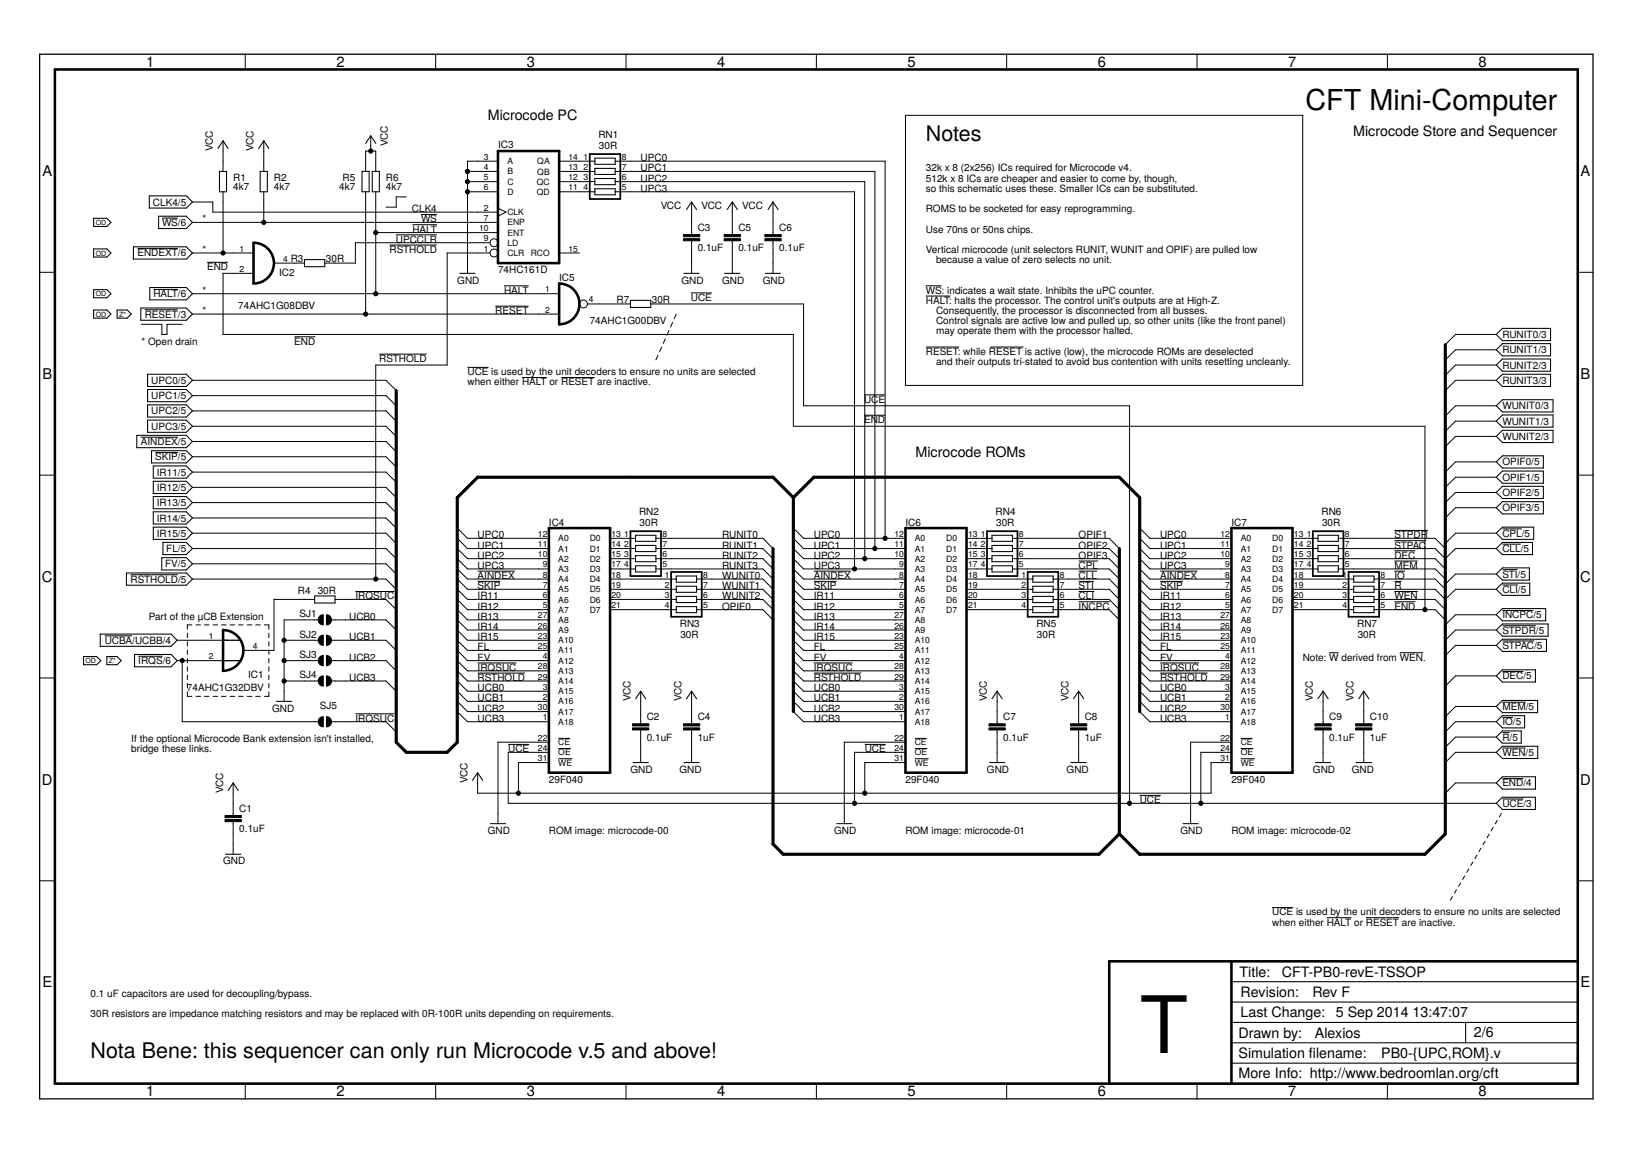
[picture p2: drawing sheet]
<svg xmlns="http://www.w3.org/2000/svg" width="297mm" height="210mm" viewBox="0 0 297 210" stroke-linecap="round" stroke-linejoin="round" font-family="sans-serif">
<defs><g id="words">
<text font-size="14.4" x="207.4" y="191.5">T</text>
<text font-size="5.2" x="237.6" y="20.1">CFT Mini-Computer</text>
<g font-size="3.9">
<text x="168.5" y="25.6">Notes</text>
<text x="16.5" y="192.5">Nota Bene: this sequencer can only run Microcode v.5 and above!</text>
</g>
<g font-size="2.7">
<text x="26.6" y="12.2">1</text>
<text x="61.2" y="12.2">2</text>
<text x="95.9" y="12.2">3</text>
<text x="130.5" y="12.2">4</text>
<text x="165.2" y="12.2">5</text>
<text x="199.8" y="12.2">6</text>
<text x="234.5" y="12.2">7</text>
<text x="269.1" y="12.2">8</text>
<text x="7.7" y="32">A</text>
<text x="287.7" y="32">A</text>
<text x="7.7" y="68.9">B</text>
<text x="287.7" y="68.9">B</text>
<text x="7.6" y="105.8">C</text>
<text x="287.6" y="105.8">C</text>
<text x="7.6" y="142.7">D</text>
<text x="287.6" y="142.7">D</text>
<text x="7.7" y="179.6">E</text>
<text x="287.7" y="179.6">E</text>
<text x="26.6" y="199.4">1</text>
<text x="61.2" y="199.4">2</text>
<text x="95.9" y="199.4">3</text>
<text x="130.5" y="199.4">4</text>
<text x="165.2" y="199.4">5</text>
<text x="199.8" y="199.4">6</text>
<text x="234.5" y="199.4">7</text>
<text x="269.1" y="199.4">8</text>
</g>
<g font-size="2.6">
<text x="88.8" y="21.9">Microcode PC</text>
<text x="246.3" y="24.7">Microcode Store and Sequencer</text>
<text x="166.7" y="83.1">Microcode ROMs</text>
<text x="225.6" y="177.6">Title:</text>
<text x="233.3" y="177.7">CFT-PB0-revE-TSSOP</text>
<text x="225.8" y="181.3">Revision:</text>
<text x="225.8" y="185">Last Change:</text>
<text x="238.9" y="181.4">Rev F</text>
<text x="243.1" y="185">5 Sep 2014</text>
<text x="257.1" y="185">13:47:07</text>
<text x="225.4" y="188.8">Drawn by:</text>
<text x="239.3" y="188.8">Alexios</text>
<text x="268.3" y="188.7">2/6</text>
<text x="225.4" y="192.5">Simulation flename:</text>
<text x="225.4" y="196.2">More Info: http://www.bedroomlan.org/cft</text>
<text x="238.2" y="192.5">i</text>
<text x="251.4" y="192.5">PB0-{UPC,ROM}.v</text>
</g>
<g font-size="1.8">
<text x="38.7" y="27.5" transform="rotate(-90 38.7 27.5)">VCC</text>
<text x="46.2" y="27.5" transform="rotate(-90 46.2 27.5)">VCC</text>
<text x="70.6" y="26.5" transform="rotate(-90 70.6 26.5)">VCC</text>
<text x="90.6" y="27">IC3</text>
<text x="108.9" y="25.1">RN1</text>
<text x="109" y="27.1">30R</text>
<text x="116.6" y="29.3">UPC0</text>
<text x="42.4" y="34.5">4k7</text>
<text x="42.4" y="32.9">R1</text>
<text x="49.9" y="34.5">4k7</text>
<text x="49.9" y="32.9">R2</text>
<text x="61.7" y="34.5">4k7</text>
<text x="62.4" y="32.9">R5</text>
<text x="70.3" y="34.5">4k7</text>
<text x="70.3" y="32.9">R6</text>
<text x="116.6" y="31.2">UPC1</text>
<text x="116.6" y="33">UPC2</text>
<text x="116.6" y="34.9">UPC3</text>
<text x="168.5" y="31.2">32k x 8 (2x256) ICs required for Microcode v4.</text>
<text x="168.5" y="33">512k x 8 ICs are cheaper and easier to come by, though,</text>
<text x="168.5" y="34.9">so this schematic uses these. Smaller ICs can be substituted.</text>
<text x="27.8" y="37.4">CLK4/5</text>
<text x="29.5" y="41.1">WS/6</text>
<text x="36.9" y="40.4">*</text>
<text x="75" y="38.6">CLK4</text>
<text x="76.6" y="40.4">WS</text>
<text x="120.3" y="38">VCC</text>
<text x="127.7" y="38">VCC</text>
<text x="135.1" y="38">VCC</text>
<text x="168.5" y="38.6">ROMS to be socketed for easy reprogramming.</text>
<text x="25" y="46.7">ENDEXT/6</text>
<text x="36.9" y="46">*</text>
<text x="52.9" y="47.7">R3</text>
<text x="59.3" y="47.7">30R</text>
<text x="70.9" y="46">RSTHOLD</text>
<text x="72" y="44.2">UPCCLR</text>
<text x="75.1" y="42.3">HALT</text>
<text x="127" y="45.7">0.1uF</text>
<text x="127" y="42">C3</text>
<text x="134.4" y="45.7">0.1uF</text>
<text x="134.4" y="42">C5</text>
<text x="141.8" y="45.7">0.1uF</text>
<text x="141.8" y="42">C6</text>
<text x="168.5" y="42.3">Use 70ns or 50ns chips.</text>
<text x="168.5" y="46">Vertical microcode (unit selectors RUNIT, WUNIT and OPIF) are pulled low</text>
<text x="170.4" y="47.9">because a value of zero selects no unit.</text>
<text x="36.9" y="53.4">*</text>
<text x="37.7" y="49.2">END</text>
<text x="50.8" y="50.2">IC2</text>
<text x="83.2" y="51.6">GND</text>
<text x="90.6" y="49.7">74HC161D</text>
<text x="91.7" y="53.4">HALT</text>
<text x="101.8" y="51.1">IC5</text>
<text x="124" y="51.6">GND</text>
<text x="131.4" y="51.6">GND</text>
<text x="138.8" y="51.6">GND</text>
<text x="168.5" y="53.4">WS: indicates a wait state. Inhibits the uPC counter.</text>
<text x="26.3" y="57.8">RESET/3</text>
<text x="27.9" y="54.1">HALT/6</text>
<text x="36.9" y="57.1">*</text>
<text x="43.4" y="56.2">74AHC1G08DBV</text>
<text x="90.2" y="57.1">RESET</text>
<text x="107.3" y="59">74AHC1G00DBV</text>
<text x="112.2" y="55.1">R7</text>
<text x="118.6" y="55.1">30R</text>
<text x="125.7" y="54.7">UCE</text>
<text x="168.5" y="55.3">HALT: halts the processor. The control unit's outputs are at High-Z.</text>
<text x="170.4" y="57.1">Consequently, the processor is disconnected from all busses.</text>
<text x="170.4" y="59">Control signals are active low and pulled up, so other units (like the front panel)</text>
<text x="25.8" y="62.7">* Open drain</text>
<text x="53.6" y="62.7">END</text>
<text x="69" y="65.8">RSTHOLD</text>
<text x="168.5" y="64.5">RESET: while RESET is active (low), the microcode ROMs are deselected</text>
<text x="170.4" y="60.8">may operate them with the processor halted.</text>
<text x="273.4" y="61.5">RUNIT0/3</text>
<text x="273.4" y="64.3">RUNIT1/3</text>
<text x="27.5" y="69.8">UPC0/5</text>
<text x="85.1" y="68.3">UCE is used by the unit decoders to ensure no units are selected</text>
<text x="85.1" y="70.1">when either HALT or RESET are inactive.</text>
<text x="170.4" y="66.4">and their outputs tri-stated to avoid bus contention with units resetting uncleanly.</text>
<text x="273.4" y="67.1">RUNIT2/3</text>
<text x="273.4" y="69.8">RUNIT3/3</text>
<text x="27.5" y="72.6">UPC1/5</text>
<text x="27.5" y="75.4">UPC2/5</text>
<text x="157.3" y="77">EN</text>
<text x="157.3" y="73.3">UCE</text>
<text x="159.8" y="77">D</text>
<text x="273.4" y="74.5">WUNIT0/3</text>
<text x="273.4" y="77.2">WUNIT1/3</text>
<text x="25.6" y="81">AINDEX/5</text>
<text x="27.5" y="78.2">UPC3/5</text>
<text x="28.3" y="83.7">SKIP/5</text>
<text x="273.4" y="80">WUNIT2/3</text>
<text x="28.5" y="86.5">IR11/5</text>
<text x="28.5" y="89.3">IR12/5</text>
<text x="273.4" y="84.7">OPIF0/5</text>
<text x="273.4" y="87.4">OPIF1/5</text>
<text x="28.5" y="92.1">IR13/5</text>
<text x="28.5" y="94.9">IR14/5</text>
<text x="99.9" y="95.6">IC4</text>
<text x="116.3" y="93.7">RN2</text>
<text x="116.4" y="95.7">30R</text>
<text x="164.8" y="95.6">IC6</text>
<text x="181.2" y="93.7">RN4</text>
<text x="181.3" y="95.7">30R</text>
<text x="224.1" y="95.6">IC7</text>
<text x="240.5" y="93.7">RN6</text>
<text x="240.6" y="95.7">30R</text>
<text x="273.4" y="90.2">OPIF2/5</text>
<text x="273.4" y="93">OPIF3/5</text>
<text x="28.5" y="97.6">IR15/5</text>
<text x="30.3" y="100.4">FL/5</text>
<text x="86.9" y="97.9">UPC0</text>
<text x="86.9" y="99.8">UPC1</text>
<text x="86.9" y="101.6">UPC2</text>
<text x="131.4" y="97.9">RUNIT0</text>
<text x="131.4" y="99.8">RUNIT1</text>
<text x="131.4" y="101.6">RUNIT2</text>
<text x="148.1" y="97.9">UPC0</text>
<text x="148.1" y="99.8">UPC1</text>
<text x="148.1" y="101.6">UPC2</text>
<text x="196.3" y="97.9">OPIF1</text>
<text x="196.3" y="99.8">OPIF2</text>
<text x="196.3" y="101.6">OPIF3</text>
<text x="211.2" y="97.9">UPC0</text>
<text x="211.2" y="99.8">UPC1</text>
<text x="211.2" y="101.6">UPC2</text>
<text x="253.8" y="97.9">STPDR</text>
<text x="253.8" y="99.8">STPAC</text>
<text x="253.8" y="101.6">DEC</text>
<text x="273.4" y="100.4">CLL/5</text>
<text x="273.4" y="97.6">CPL/5</text>
<text x="23.8" y="106">RSTHOLD/5</text>
<text x="30.1" y="103.2">FV/5</text>
<text x="86.9" y="105.3">AINDEX</text>
<text x="86.9" y="107.2">SKIP</text>
<text x="86.9" y="103.5">UPC3</text>
<text x="131.4" y="103.5">RUNIT3</text>
<text x="131.4" y="105.3">WUNIT0</text>
<text x="131.4" y="107.2">WUNIT1</text>
<text x="148.1" y="105.3">AINDEX</text>
<text x="148.1" y="107.2">SKIP</text>
<text x="148.1" y="103.5">UPC3</text>
<text x="196.3" y="107.2">STI</text>
<text x="196.3" y="105.3">CLL</text>
<text x="196.3" y="103.5">CPL</text>
<text x="211.2" y="105.3">AINDEX</text>
<text x="211.2" y="107.2">SKIP</text>
<text x="211.2" y="103.5">UPC3</text>
<text x="253.8" y="103.5">MEM</text>
<text x="253.8" y="105.3">IO</text>
<text x="253.8" y="107.2">R</text>
<text x="273.4" y="107.8">CLI/5</text>
<text x="273.4" y="105.1">STI/5</text>
<text x="27.1" y="112.7">Part of the µCB Extension</text>
<text x="54.2" y="108.1">R4</text>
<text x="54.5" y="112.3">SJ1</text>
<text x="57.8" y="108.1">30R</text>
<text x="63.6" y="112.7">UCB0</text>
<text x="64.7" y="109">IRQSUC</text>
<text x="86.9" y="109">IR11</text>
<text x="86.9" y="110.9">IR12</text>
<text x="86.9" y="112.7">IR13</text>
<text x="131.4" y="109">WUNIT2</text>
<text x="131.4" y="110.9">OPIF0</text>
<text x="148.1" y="109">IR11</text>
<text x="148.1" y="110.9">IR12</text>
<text x="148.1" y="112.7">IR13</text>
<text x="196.3" y="110.9">INCPC</text>
<text x="196.3" y="109">CLI</text>
<text x="211.2" y="109">IR11</text>
<text x="211.2" y="110.9">IR12</text>
<text x="211.2" y="112.7">IR13</text>
<text x="253.8" y="109">WEN</text>
<text x="253.8" y="110.9">END</text>
<text x="273.4" y="112.5">INCPC/5</text>
<text x="19.1" y="117.1">UCBA/UCBB/4</text>
<text x="54.5" y="116">SJ2</text>
<text x="54.5" y="119.7">SJ3</text>
<text x="63.6" y="116.5">UCB1</text>
<text x="86.9" y="114.6">IR14</text>
<text x="86.9" y="116.5">IR15</text>
<text x="86.9" y="118.3">FL</text>
<text x="123.7" y="114">RN3</text>
<text x="123.8" y="116.1">30R</text>
<text x="148.1" y="114.6">IR14</text>
<text x="148.1" y="116.5">IR15</text>
<text x="148.1" y="118.3">FL</text>
<text x="188.6" y="114">RN5</text>
<text x="188.7" y="116.1">30R</text>
<text x="211.2" y="114.6">IR14</text>
<text x="211.2" y="116.5">IR15</text>
<text x="211.2" y="118.3">FL</text>
<text x="247" y="114">RN7</text>
<text x="247.1" y="116.1">30R</text>
<text x="273.4" y="115.3">STPDR/5</text>
<text x="273.4" y="118">STPAC/5</text>
<text x="25.2" y="120.8">IRQS/6</text>
<text x="34" y="125.7">74AHC1G32DBV</text>
<text x="45.2" y="123.4">IC1</text>
<text x="54.5" y="123.4">SJ4</text>
<text x="63.6" y="120.2">UCB2</text>
<text x="63.6" y="123.9">UCB3</text>
<text x="86.9" y="123.9">RSTHOLD</text>
<text x="86.9" y="120.2">FV</text>
<text x="86.9" y="125.7">UCB0</text>
<text x="86.9" y="122">IRQSUC</text>
<text x="148.1" y="123.9">RSTHOLD</text>
<text x="148.1" y="120.2">FV</text>
<text x="148.1" y="125.7">UCB0</text>
<text x="148.1" y="122">IRQSUC</text>
<text x="211.2" y="123.9">RSTHOLD</text>
<text x="211.2" y="120.2">FV</text>
<text x="211.2" y="125.7">UCB0</text>
<text x="211.2" y="122">IRQSUC</text>
<text x="237.1" y="120.2">Note: W derived from WEN.</text>
<text x="273.4" y="123.6">DEC/5</text>
<text x="49.5" y="129.4">GND</text>
<text x="58.2" y="129">SJ5</text>
<text x="64.7" y="131.3">IRQSUC</text>
<text x="86.9" y="127.6">UCB1</text>
<text x="86.9" y="129.4">UCB2</text>
<text x="86.9" y="131.3">UCB3</text>
<text x="114.7" y="127.6" transform="rotate(-90 114.7 127.6)">VCC</text>
<text x="117.7" y="131">C2</text>
<text x="124" y="127.6" transform="rotate(-90 124 127.6)">VCC</text>
<text x="127" y="131">C4</text>
<text x="148.1" y="127.6">UCB1</text>
<text x="148.1" y="129.4">UCB2</text>
<text x="148.1" y="131.3">UCB3</text>
<text x="179.6" y="127.6" transform="rotate(-90 179.6 127.6)">VCC</text>
<text x="182.6" y="131">C7</text>
<text x="194.5" y="127.6" transform="rotate(-90 194.5 127.6)">VCC</text>
<text x="197.4" y="131">C8</text>
<text x="211.2" y="127.6">UCB1</text>
<text x="211.2" y="129.4">UCB2</text>
<text x="211.2" y="131.3">UCB3</text>
<text x="239" y="127.6" transform="rotate(-90 239 127.6)">VCC</text>
<text x="241.9" y="131">C9</text>
<text x="246.4" y="127.6" transform="rotate(-90 246.4 127.6)">VCC</text>
<text x="249.3" y="131">C10</text>
<text x="273.4" y="129.2">MEM/5</text>
<text x="273.4" y="131.9">IO/5</text>
<text x="23.9" y="135">If the optional Microcode Bank extension isn't installed,</text>
<text x="23.9" y="136.8">bridge these links.</text>
<text x="92.5" y="136.8">UCE</text>
<text x="117.7" y="134.7">0.1uF</text>
<text x="127" y="134.7">1uF</text>
<text x="157.4" y="136.8">UCE</text>
<text x="182.6" y="134.7">0.1uF</text>
<text x="197.4" y="134.7">1uF</text>
<text x="241.9" y="134.7">0.1uF</text>
<text x="249.3" y="134.7">1uF</text>
<text x="273.4" y="134.7">R/5</text>
<text x="273.4" y="137.5">WEN/5</text>
<text x="85.1" y="142.4" transform="rotate(-90 85.1 142.4)">VCC</text>
<text x="99.9" y="142.4">29F040</text>
<text x="114.7" y="140.6">GND</text>
<text x="123.7" y="140.6">GND</text>
<text x="164.8" y="142.4">29F040</text>
<text x="179.6" y="140.6">GND</text>
<text x="194.1" y="140.6">GND</text>
<text x="224.1" y="142.4">29F040</text>
<text x="239" y="140.6">GND</text>
<text x="246" y="140.6">GND</text>
<text x="273.4" y="143.1">END/4</text>
<text x="40.6" y="144.3" transform="rotate(-90 40.6 144.3)">VCC</text>
<text x="43.6" y="147.7">C1</text>
<text x="207.4" y="146.1">UCE</text>
<text x="273.4" y="146.8">UCE/3</text>
<text x="43.6" y="151.4">0.1uF</text>
<text x="88.8" y="151.7">GND</text>
<text x="99.9" y="151.7">ROM image: microcode-00</text>
<text x="151.8" y="151.7">GND</text>
<text x="164.8" y="151.7">ROM image: microcode-01</text>
<text x="214.9" y="151.7">GND</text>
<text x="224.1" y="151.7">ROM image: microcode-02</text>
<text x="40.6" y="157.2">GND</text>
<text x="231.5" y="166.5">UCE is used by the unit decoders to ensure no units are selected</text>
<text x="231.5" y="168.4">when either HALT or RESET are inactive.</text>
<text x="16.5" y="185">30R resistors are impedance matching resistors and may be replaced with 0R-100R units depending on requirements.</text>
<text x="16.5" y="181.3">0.1 uF capacitors are used for decoupling/bypass.</text>
</g>
<g font-size="1.6">
<text x="88.1" y="29.1">3</text>
<text x="92.4" y="29.9">A</text>
<text x="97.8" y="29.9">QA</text>
<text x="103.5" y="29.1">14</text>
<text x="106.2" y="29.1">1</text>
<text x="113.2" y="29.1">8</text>
<text x="88.1" y="30.9">4</text>
<text x="88.1" y="32.8">5</text>
<text x="88.1" y="34.6">6</text>
<text x="92.4" y="31.7">B</text>
<text x="92.4" y="33.6">C</text>
<text x="92.4" y="35.4">D</text>
<text x="97.7" y="35.5">QD</text>
<text x="97.7" y="33.6">QC</text>
<text x="97.8" y="31.7">QB</text>
<text x="103.5" y="34.6">11</text>
<text x="103.5" y="32.8">12</text>
<text x="103.5" y="30.9">13</text>
<text x="106.2" y="30.9">2</text>
<text x="106.2" y="32.8">3</text>
<text x="106.2" y="34.6">4</text>
<text x="113.2" y="34.6">5</text>
<text x="113.2" y="32.8">6</text>
<text x="113.2" y="30.9">7</text>
<text x="88.1" y="38.3">2</text>
<text x="88.1" y="40.2">7</text>
<text x="92.4" y="39.2">CLK</text>
<text x="92.4" y="41">ENP</text>
<text x="43.6" y="45.8">1</text>
<text x="51.6" y="47.6">4</text>
<text x="87.2" y="42">10</text>
<text x="88.1" y="45.8">1</text>
<text x="88.1" y="43.9">9</text>
<text x="92.4" y="46.6">CLR</text>
<text x="92.4" y="44.7">LD</text>
<text x="92.4" y="42.9">ENT</text>
<text x="96.6" y="46.6">RCO</text>
<text x="103.5" y="45.8">15</text>
<text x="43.6" y="49.5">2</text>
<text x="99.2" y="53.2">1</text>
<text x="99.2" y="56.9">2</text>
<text x="107.2" y="55">4</text>
<text x="97.9" y="101.4">10</text>
<text x="97.9" y="99.5">11</text>
<text x="97.9" y="97.7">12</text>
<text x="101.6" y="100.3">A1</text>
<text x="101.6" y="98.5">A0</text>
<text x="107.3" y="98.5">D0</text>
<text x="107.3" y="100.3">D1</text>
<text x="111.3" y="97.7">13</text>
<text x="111.3" y="99.5">14</text>
<text x="111.3" y="101.4">15</text>
<text x="113.6" y="99.5">2</text>
<text x="113.6" y="101.4">3</text>
<text x="113.6" y="97.7">1</text>
<text x="120.6" y="101.4">6</text>
<text x="120.6" y="99.5">7</text>
<text x="120.6" y="97.7">8</text>
<text x="162.8" y="101.4">10</text>
<text x="162.8" y="99.5">11</text>
<text x="162.8" y="97.7">12</text>
<text x="166.5" y="100.3">A1</text>
<text x="166.5" y="98.5">A0</text>
<text x="172.2" y="98.5">D0</text>
<text x="172.2" y="100.3">D1</text>
<text x="176.2" y="97.7">13</text>
<text x="176.2" y="99.5">14</text>
<text x="176.2" y="101.4">15</text>
<text x="178.5" y="99.5">2</text>
<text x="178.5" y="101.4">3</text>
<text x="178.5" y="97.7">1</text>
<text x="185.5" y="101.4">6</text>
<text x="185.5" y="99.5">7</text>
<text x="185.5" y="97.7">8</text>
<text x="222.1" y="101.4">10</text>
<text x="222.1" y="99.5">11</text>
<text x="222.1" y="97.7">12</text>
<text x="225.8" y="100.3">A1</text>
<text x="225.8" y="98.5">A0</text>
<text x="231.6" y="98.5">D0</text>
<text x="231.6" y="100.3">D1</text>
<text x="235.5" y="97.7">13</text>
<text x="235.5" y="99.5">14</text>
<text x="235.5" y="101.4">15</text>
<text x="237.8" y="99.5">2</text>
<text x="237.8" y="101.4">3</text>
<text x="237.8" y="97.7">1</text>
<text x="244.8" y="101.4">6</text>
<text x="244.8" y="99.5">7</text>
<text x="244.8" y="97.7">8</text>
<text x="98.8" y="106.9">7</text>
<text x="98.8" y="105.1">8</text>
<text x="98.8" y="103.2">9</text>
<text x="101.6" y="107.7">A5</text>
<text x="101.6" y="105.9">A4</text>
<text x="101.6" y="104">A3</text>
<text x="101.6" y="102.2">A2</text>
<text x="107.3" y="102.2">D2</text>
<text x="107.3" y="104">D3</text>
<text x="107.3" y="105.9">D4</text>
<text x="107.3" y="107.8">D5</text>
<text x="111.3" y="103.2">17</text>
<text x="111.3" y="105.1">18</text>
<text x="111.3" y="106.9">19</text>
<text x="113.6" y="103.2">4</text>
<text x="120.6" y="103.2">5</text>
<text x="121" y="106.9">2</text>
<text x="121" y="105.1">1</text>
<text x="128" y="106.9">7</text>
<text x="128" y="105.1">8</text>
<text x="163.7" y="106.9">7</text>
<text x="163.7" y="105.1">8</text>
<text x="163.7" y="103.2">9</text>
<text x="166.5" y="107.7">A5</text>
<text x="166.5" y="105.9">A4</text>
<text x="166.5" y="104">A3</text>
<text x="166.5" y="102.2">A2</text>
<text x="172.2" y="102.2">D2</text>
<text x="172.2" y="104">D3</text>
<text x="172.2" y="105.9">D4</text>
<text x="172.2" y="107.8">D5</text>
<text x="176.2" y="103.2">17</text>
<text x="176.2" y="105.1">18</text>
<text x="176.2" y="106.9">19</text>
<text x="178.5" y="103.2">4</text>
<text x="185.5" y="103.2">5</text>
<text x="185.9" y="106.9">2</text>
<text x="185.9" y="105.1">1</text>
<text x="192.9" y="106.9">7</text>
<text x="192.9" y="105.1">8</text>
<text x="223" y="106.9">7</text>
<text x="223" y="105.1">8</text>
<text x="223" y="103.2">9</text>
<text x="225.8" y="107.7">A5</text>
<text x="225.8" y="105.9">A4</text>
<text x="225.8" y="104">A3</text>
<text x="225.8" y="102.2">A2</text>
<text x="231.6" y="102.2">D2</text>
<text x="231.6" y="104">D3</text>
<text x="231.6" y="105.9">D4</text>
<text x="231.6" y="107.8">D5</text>
<text x="235.5" y="103.2">17</text>
<text x="235.5" y="105.1">18</text>
<text x="235.5" y="106.9">19</text>
<text x="237.8" y="103.2">4</text>
<text x="244.3" y="106.9">2</text>
<text x="244.3" y="105.1">1</text>
<text x="244.8" y="103.2">5</text>
<text x="251.3" y="106.9">7</text>
<text x="251.3" y="105.1">8</text>
<text x="97.9" y="112.5">27</text>
<text x="98.8" y="110.6">5</text>
<text x="98.8" y="108.8">6</text>
<text x="101.6" y="111.4">A7</text>
<text x="101.6" y="109.6">A6</text>
<text x="101.6" y="113.3">A8</text>
<text x="107.3" y="109.6">D6</text>
<text x="107.3" y="111.5">D7</text>
<text x="111.3" y="108.8">20</text>
<text x="111.3" y="110.6">21</text>
<text x="121" y="108.8">3</text>
<text x="121" y="110.6">4</text>
<text x="128" y="110.6">5</text>
<text x="128" y="108.8">6</text>
<text x="162.8" y="112.5">27</text>
<text x="163.7" y="110.6">5</text>
<text x="163.7" y="108.8">6</text>
<text x="166.5" y="111.4">A7</text>
<text x="166.5" y="109.6">A6</text>
<text x="166.5" y="113.3">A8</text>
<text x="172.2" y="109.6">D6</text>
<text x="172.2" y="111.5">D7</text>
<text x="176.2" y="108.8">20</text>
<text x="176.2" y="110.6">21</text>
<text x="185.9" y="108.8">3</text>
<text x="185.9" y="110.6">4</text>
<text x="192.9" y="110.6">5</text>
<text x="192.9" y="108.8">6</text>
<text x="222.1" y="112.5">27</text>
<text x="223" y="110.6">5</text>
<text x="223" y="108.8">6</text>
<text x="225.8" y="111.4">A7</text>
<text x="225.8" y="109.6">A6</text>
<text x="225.8" y="113.3">A8</text>
<text x="231.6" y="109.6">D6</text>
<text x="231.6" y="111.5">D7</text>
<text x="235.5" y="108.8">20</text>
<text x="235.5" y="110.6">21</text>
<text x="244.3" y="108.8">3</text>
<text x="244.3" y="110.6">4</text>
<text x="251.3" y="110.6">5</text>
<text x="251.3" y="108.8">6</text>
<text x="38" y="116.2">1</text>
<text x="38" y="119.9">2</text>
<text x="46" y="118">4</text>
<text x="97.9" y="116.2">23</text>
<text x="97.9" y="118">25</text>
<text x="97.9" y="114.3">26</text>
<text x="98.8" y="119.9">4</text>
<text x="101.6" y="117">A10</text>
<text x="101.6" y="118.9">A11</text>
<text x="101.6" y="115.2">A9</text>
<text x="162.8" y="116.2">23</text>
<text x="162.8" y="118">25</text>
<text x="162.8" y="114.3">26</text>
<text x="163.7" y="119.9">4</text>
<text x="166.5" y="117">A10</text>
<text x="166.5" y="118.9">A11</text>
<text x="166.5" y="115.2">A9</text>
<text x="222.1" y="116.2">23</text>
<text x="222.1" y="118">25</text>
<text x="222.1" y="114.3">26</text>
<text x="223" y="119.9">4</text>
<text x="225.8" y="117">A10</text>
<text x="225.8" y="118.9">A11</text>
<text x="225.8" y="115.2">A9</text>
<text x="97.9" y="121.8">28</text>
<text x="97.9" y="123.6">29</text>
<text x="98.8" y="125.5">3</text>
<text x="101.6" y="120.7">A12</text>
<text x="101.6" y="122.6">A13</text>
<text x="101.6" y="124.4">A14</text>
<text x="162.8" y="121.8">28</text>
<text x="162.8" y="123.6">29</text>
<text x="163.7" y="125.5">3</text>
<text x="166.5" y="120.7">A12</text>
<text x="166.5" y="122.6">A13</text>
<text x="166.5" y="124.4">A14</text>
<text x="222.1" y="121.8">28</text>
<text x="222.1" y="123.6">29</text>
<text x="223" y="125.5">3</text>
<text x="225.8" y="120.7">A12</text>
<text x="225.8" y="122.6">A13</text>
<text x="225.8" y="124.4">A14</text>
<text x="97.9" y="129.2">30</text>
<text x="98.8" y="127.3">2</text>
<text x="98.8" y="131">1</text>
<text x="101.6" y="126.3">A15</text>
<text x="101.6" y="128.1">A16</text>
<text x="101.6" y="130">A17</text>
<text x="101.6" y="131.8">A18</text>
<text x="162.8" y="129.2">30</text>
<text x="163.7" y="127.3">2</text>
<text x="163.7" y="131">1</text>
<text x="166.5" y="126.3">A15</text>
<text x="166.5" y="128.1">A16</text>
<text x="166.5" y="130">A17</text>
<text x="166.5" y="131.8">A18</text>
<text x="222.1" y="129.2">30</text>
<text x="223" y="127.3">2</text>
<text x="223" y="131">1</text>
<text x="225.8" y="126.3">A15</text>
<text x="225.8" y="128.1">A16</text>
<text x="225.8" y="130">A17</text>
<text x="225.8" y="131.8">A18</text>
<text x="97.9" y="134.7">22</text>
<text x="97.9" y="136.6">24</text>
<text x="101.6" y="135.5">CE</text>
<text x="101.6" y="137.4">OE</text>
<text x="162.8" y="134.7">22</text>
<text x="162.8" y="136.6">24</text>
<text x="166.5" y="135.5">CE</text>
<text x="166.5" y="137.4">OE</text>
<text x="222.1" y="134.7">22</text>
<text x="222.1" y="136.6">24</text>
<text x="225.8" y="135.5">CE</text>
<text x="225.8" y="137.4">OE</text>
<text x="97.9" y="138.4">31</text>
<text x="101.6" y="139.3">WE</text>
<text x="162.8" y="138.4">31</text>
<text x="166.5" y="139.3">WE</text>
<text x="222.1" y="138.4">31</text>
<text x="225.8" y="139.3">WE</text>
</g>
<g font-size="1.3">
<text x="17.4" y="40.9">OD</text>
<text x="17.4" y="46.5">OD</text>
<text x="17.4" y="53.9">OD</text>
<text x="17.4" y="57.6">OD</text>
<text x="21.7" y="57.6">Z*</text>
<text x="15.6" y="120.6">OD</text>
<text x="19.8" y="120.6">Z*</text>
</g>
</g></defs>
<g fill="none" stroke="#000" stroke-width=".18">
<path d="M10 12.6h277.2v184.5h-277.2zM44.6 9.9v2.7M79.3 9.9v2.7M113.9 9.9v2.7M148.6 9.9v2.7M183.2 9.9v2.7M217.9 9.9v2.7M252.5 9.9v2.7M29.5 39.7h2.9M35 36.7h3.7v1.9h51.9M40.6 25.6v5.6M40.6 34.9v11.1"/>
<path d="M48 25.6v5.6M48 34.9v5.5M66.5 31.2v-3.7h1.9v3.7M66.5 34.9v22.2M67.5 24.7v2.8M68.4 34.9v18.5M74 35.8h-1.9v1.9h-1.8M76.6 39h2.9M85.1 31.2h5.5M85.1 33h5.5M85.1 34.9h5.5M90.6 29.3h-5.5v20.4"/>
<path d="M90.6 37.9l1.5 .7-1.5 .7M101.8 29.3h6.5M101.8 31.2h6.5M101.8 33h6.5M101.8 34.9h6.5M112 29.3h49.1v68.6M112 31.2h47.2v68.6M112 33h45.4v68.6M112 34.9h43.5v68.6M125.9 36.7v6M133.3 36.7v6M140.7 36.7v6"/>
<path d="M164.8 21h72.3v49.1h-72.3zM7.2 49.5h2.8M25 45.2h7.4M25.8 59h3.7v1.8h.9v-1.8h2.8M26.3 56.3h6.1M27.9 52.6h4.5M35 46h11.1M35 40.4h55.6M35 53.4h66.8M35 57.1h66.8M37.7 47.7h3.8M46.1 49.7h-5.5v11.1h103.8v16.7h115v33.4"/>
<path d="M49.9 47.9h5.5M68.4 42.3h22.2M70.9 44.6h8.6M72.1 42.7h7.4M75.1 40.9h4.4M89.2 46h-7.8v20.4h-13v38.9M89.2 44.2h-24.5v3.7h-5.6M90.1 55.7h6.1M91.7 52h4.5M101.8 46h3.7M106.9 55.3h7.8M118.4 55.3h27.9v18.5h59.3v72.3"/>
<path d="M122.4 58.6l-.4 .9M123.1 57.1l-.4 .9M125.8 53.3h3.8M125.9 43.8v5.9M133.3 43.8v5.9M140.7 43.8v5.9M168.5 52h2.9M168.5 53.8h4.5M287.2 49.5h2.7M25.6 79.5h6.8M35 69.2h35.3l1.8 1.8M35 77.5h35.3l1.8 1.9"/>
<path d="M35 72h35.3l1.8 1.8M35 74.7h35.3l1.8 1.9M53.6 61.3h3.8M69 64.4h8.7M85.1 66.8h3.8M95 68.7h4.5M102.2 68.7h6M119.8 64.6l-.4 .9M120.4 63.1l-.3 .9M121.1 61.6l-.4 .9M121.8 60.1l-.4 .9M157.3 75.5h3.8"/>
<path d="M157.3 71.8h3.8M168.5 63.1h6.1M180.2 63.1h6.1M272.3 60.8h-7.4l-1.8 1.9M272.3 66.4h-7.4l-1.8 1.9M272.3 63.6h-7.4l-1.8 1.9M272.3 69.2h-7.4l-1.8 1.8M272.3 73.8h-7.4l-1.8 1.9M272.3 76.6h-7.4l-1.8 1.8M272.3 79.4h-7.4l-1.8 1.8M7.2 86.4h2.8M28.3 82.3h4.1"/>
<path d="M35 99.8h35.3l1.8 1.8M35 80.3h35.3l1.8 1.9M35 83.1h35.3l1.8 1.8M35 85.9h35.3l1.8 1.8M35 88.6h35.3l1.8 1.9M35 91.4h35.3l1.8 1.9M35 94.2h35.3l1.8 1.9M35 97h35.3l1.8 1.8M83.2 99.8l1.9 1.8h14.8M83.2 97.9l1.9 1.9h14.8M83.2 96.1l1.9 1.8h14.8M111 99.8h4.7"/>
<path d="M111 97.9h4.7M119.4 99.8h19.5l1.8 1.8M119.4 97.9h19.5l1.8 1.9M144.4 99.8l1.9 1.8h18.5M144.4 97.9l1.9 1.9h18.5M144.4 96.1l1.9 1.8h18.5M175.9 99.8h4.7M175.9 97.9h4.7M184.3 99.8h17.6l1.8 1.8M184.3 97.9h17.6l1.8 1.9M207.4 99.8l1.9 1.8h14.8M207.4 97.9l1.9 1.9h14.8"/>
<path d="M207.4 96.1l1.9 1.8h14.8M235.2 99.8h4.7M235.2 97.9h4.7M243.6 99.8h17.6l1.9 1.8 1.8-1.8h7.4M243.6 97.9h17.6l1.9 1.9M253.8 96.5h6.1M253.8 98.3h5.8M272.3 97h-7.4l-1.8 1.8M272.3 84h-7.4l-1.8 1.9M272.3 86.8h-7.4l-1.8 1.8M272.3 89.6h-7.4l-1.8 1.8M272.3 92.4h-7.4l-1.8 1.8"/>
<path d="M273.5 99h3.3M273.5 96.2h3.5M287.2 86.4h2.7M19.1 115.7h5M23.7 104.5h8.7M25.2 119.4h4.4M32.2 116.5h9.3M34.1 115.2v.8M34.1 116.7v.8M34.1 118.2v.8M34.1 119.8v.8M34.9 113.7h-.8v.8"/>
<path d="M35 105.3h35.3l1.8 1.9M35 102.6h35.3l1.8 1.8M35.7 113.7h.8M37.2 113.7h.8M38.8 113.7h.8M40.3 113.7h.8M41.9 113.7h.8M43.4 113.7h.9M45 113.7h.8M46.5 113.7h.9M48.1 113.7h.8v.8M48.9 115.2v.8"/>
<path d="M48.9 116.7v.8M48.9 118.2v.8M48.9 119.8v.8M51.7 116.5h6.2M57.3 109h-7.4v9.3h-5.6M57.9 112.8h-6.2v14.8M60.3 116.5h10l1.8 1.8M60.3 112.8h10l1.8 1.8M61 109h9.3l1.8 1.9M64.7 107.6h7.1M83.2 118.3l1.9 1.9h14.8M83.2 109l1.9 1.9h14.8"/>
<path d="M83.2 107.2l1.9 1.8h14.8M83.2 105.3l1.9 1.9h14.8M83.2 103.5l1.9 1.8h14.8M83.2 101.6l1.9 1.9h14.8M83.2 114.6l1.9 1.9h14.8M83.2 116.5l1.9 1.8h14.8M83.2 112.8l1.9 1.8h14.8M83.2 110.9l1.9 1.9h14.8M86.9 103.9h6.8M86.9 105.7h4.2M111 110.9h12.1M111 109h12.1"/>
<path d="M111 107.2h12.1M111 105.3h12.1M111 103.5h4.7M111 101.6h4.7M119.4 103.5h19.5l1.8 1.8M119.4 101.6h19.5l1.8 1.9M126.8 110.9h12.1l1.8 1.9M126.8 109h12.1l1.8 1.9M126.8 107.2h12.1l1.8 1.8M126.8 105.3h12.1l1.8 1.9M144.4 118.3l1.9 1.9h18.5M144.4 109l1.9 1.9h18.5"/>
<path d="M144.4 107.2l1.9 1.8h18.5M144.4 105.3l1.9 1.9h18.5M144.4 103.5l1.9 1.8h18.5M144.4 101.6l1.9 1.9h18.5M144.4 114.6l1.9 1.9h18.5M144.4 116.5l1.9 1.8h18.5M144.4 112.8l1.9 1.8h18.5M144.4 110.9l1.9 1.9h18.5M148.1 103.9h6.8M148.1 105.7h4.2M175.9 110.9h12.1M175.9 109h12.1"/>
<path d="M175.9 107.2h12.1M175.9 105.3h12.1M175.9 103.5h4.7M175.9 101.6h4.7M184.3 103.5h17.6l1.8 1.8M184.3 101.6h17.6l1.8 1.9M191.7 110.9h10.2l1.8 1.9M191.7 109h10.2l1.8 1.9M191.7 107.2h10.2l1.8 1.8M191.7 105.3h10.2l1.8 1.9M196.3 103.9h3.4M196.3 105.7h2.8"/>
<path d="M196.3 102h3.6M196.3 107.6h2.9M196.3 109.5h5.7M207.4 118.3l1.9 1.9h14.8M207.4 109l1.9 1.9h14.8M207.4 107.2l1.9 1.8h14.8M207.4 105.3l1.9 1.9h14.8M207.4 103.5l1.9 1.8h14.8M207.4 101.6l1.9 1.9h14.8M207.4 114.6l1.9 1.9h14.8M207.4 116.5l1.9 1.8h14.8M207.4 112.8l1.9 1.8h14.8"/>
<path d="M207.4 110.9l1.9 1.9h14.8M211.2 103.9h6.7M211.2 105.7h4.1M235.2 110.9h11.2M235.2 109h11.2M235.2 107.2h11.2M235.2 105.3h11.2M235.2 103.5h4.7M235.2 101.6h4.7M241.9 118.7h1.7M243.6 103.5h17.6l1.9 1.8M243.6 101.6h17.6l1.9 1.9"/>
<path d="M250.1 110.9h11.1l1.9 1.9M250.1 109h11.1l1.9 1.9M250.1 107.2h11.1l1.9 1.8 1.8-1.8h7.4M250.1 105.3h11.1l1.9 1.9M253.8 103.9h1.9M253.8 105.7h1.3M253.8 102h4.2M253.8 107.6h4.2M253.8 109.5h3.8M253.8 100.2h3.8M254.8 118.7h4.2M272.3 114.6h-7.4l-1.8 1.9"/>
<path d="M272.3 111.8h-7.4l-1.8 1.9M272.3 104.4h-7.4l-1.8 1.9M272.3 117.4h-7.4l-1.8 1.8M273.5 111h5.6M273.5 106.4h2.8M273.5 103.6h2.7M273.5 113.8h6M273.5 116.6h5.8M7.2 123.3h2.8M32.2 120.2h9.3M33.2 120.2v11.1h24.7M34.1 121.3v.8"/>
<path d="M34.1 122.8v.8M34.1 124.3v.8M34.1 125.9v.8h.8M35.7 126.7h.8M37.2 126.7h.8M38.8 126.7h.8M40.3 126.7h.8M41.9 126.7h.8M43.4 126.7h.9M45 126.7h.8M46.5 126.7h.9M48.9 125.9v.8h-.8"/>
<path d="M48.9 121.3v.8M48.9 122.8v.8M48.9 124.3v.8M51.7 120.2h6.2M51.7 123.9h6.2M60.3 120.2h10l1.8 1.8M60.3 123.9h10l1.8 1.8M60.3 131.3h10l1.8 1.8M64.7 129.8h7.1M83.2 120.2l1.9 1.8h14.8M83.2 122l1.9 1.9h14.8M83.2 123.9l1.9 1.8h14.8"/>
<path d="M83.2 125.7l1.9 1.9h14.8M83.2 127.6l1.9 1.8h14.8M83.2 129.4l1.9 1.9h14.8M86.9 122.4h8.7M86.9 120.6h7.1M92.5 135.4h3.8M99.9 138.7h-5.5v5.6M99.9 135h-9.3v14.8M99.9 136.8h-7.4v9.3h179.8M101.6 138h2.5M101.6 134.3h2.2M101.6 136.1h2.3"/>
<path d="M116.6 125.7v6M116.6 132.8v5.9M125.9 125.7v6M125.9 132.8v5.9M144.4 120.2l1.9 1.8h18.5M144.4 122l1.9 1.9h18.5M144.4 123.9l1.9 1.8h18.5M144.4 125.7l1.9 1.9h18.5M144.4 127.6l1.9 1.8h18.5M144.4 129.4l1.9 1.9h18.5M148.1 122.4h8.7M148.1 120.6h7.1"/>
<path d="M157.4 135.4h3.8M164.8 138.7h-7.4v5.6M164.8 135h-11.1v14.8M164.8 136.8h-9.3v9.3M166.5 138h2.5M166.5 134.3h2.2M166.5 136.1h2.3M181.5 125.7v6M181.5 132.8v5.9M196.3 125.7v6M196.3 132.8v5.9M207.4 120.2l1.9 1.8h14.8"/>
<path d="M207.4 122l1.9 1.9h14.8M207.4 123.9l1.9 1.8h14.8M207.4 125.7l1.9 1.9h14.8M207.4 127.6l1.9 1.8h14.8M207.4 129.4l1.9 1.9h14.8M211.2 122.4h8.6M211.2 120.6h7M224.1 138.7h-3.7v5.6h-133.5v-3.8M224.1 135h-7.4v14.8M224.1 136.8h-5.5v9.3M225.8 138h2.5M225.8 134.3h2.2"/>
<path d="M225.8 136.1h2.3M240.8 125.7v6M240.8 132.8v5.9M248.2 125.7v6M248.2 132.8v5.9M272.3 136.8h-7.4l-1.8 1.9M272.3 131.3h-7.4l-1.8 1.8M272.3 128.5h-7.4l-1.8 1.9M272.3 134.1h-7.4l-1.8 1.8M272.3 122.9h-7.4l-1.8 1.9M273.5 127.7h4.2M273.5 130.5h1.9"/>
<path d="M273.5 133.3h1.3M273.5 136.1h4.2M273.5 122.2h3.8M287.2 123.3h2.7M42.4 142.4v5.9M42.4 149.5v5.9M207.4 144.7h3.9M266.6 159.3l-.4 .7M267.3 158.1l-.3 .6M268.1 156.8l-.4 .6M268.8 155.5l-.4 .7M269.6 154.3l-.4 .6"/>
<path d="M270.3 153l-.4 .6M271 151.7l-.3 .7M271.8 150.5l-.4 .6M272.3 142.4h-7.4l-1.8 1.9M272.5 149.2l-.4 .7M273.3 148l-.4 .6M273.5 141.6h3.8M273.5 145.3h3.8M7.2 160.2h2.8M231.5 165.1h3.9M241.5 166.9h4.5M248.6 166.9h6.1"/>
<path d="M264.4 163.1l-.4 .6M265.1 161.8l-.4 .7M265.9 160.6l-.4 .6M287.2 160.2h2.7M44.6 197.1v2.8M79.3 197.1v2.8M113.9 197.1v2.8M148.6 197.1v2.8M183.2 197.1v2.8M217.9 197.1v2.8M252.5 197.1v2.8M287.2 197h.1"/>
<circle cx="89.9" cy="46" r=".72"/>
<circle cx="89.9" cy="44.2" r=".72"/>
<circle cx="106.2" cy="55.3" r=".72"/>
</g>
<g fill="none" stroke="#000" stroke-width=".19">
<path d="M17 39.7h2.5l.7 .7-.7 .8h-2.5zM27.2 35.6h6.7l1.1 1.1-1.1 1.1h-6.7zM28.9 39.3h5l1.1 1.1-1.1 1.2h-5zM39.7 27l.9-1.4 .9 1.4M39.9 31.2h1.3v3.7h-1.3zM47.1 27l.9-1.4 .9 1.4M47.3 31.2h1.4v3.7h-1.4zM65.9 31.2h1.3v3.7h-1.3zM66.5 26.1l1-1.4 .9 1.4M67.8 31.2h1.2v3.7h-1.2zM108.3 28.8h3.7v1.1h-3.7zM108.3 30.6h3.7v1.1h-3.7z"/>
<path d="M108.3 32.5h3.7v1.1h-3.7zM108.3 34.3h3.7v1.1h-3.7zM124.9 38.1l1-1.4 .9 1.4M132.4 38.1l.9-1.4 .9 1.4M139.8 38.1l.9-1.4 .9 1.4M17 56.4h2.5l.7 .7-.7 .8h-2.5zM17 52.7h2.5l.7 .7-.7 .8h-2.5zM17 45.3h2.5l.7 .7-.7 .8h-2.5zM21.3 56.4h1.9l.7 .7-.7 .8h-1.9zM24.3 44.9h9.6l1.1 1.1-1.1 1.1h-9.6zM25.6 56h8.3l1.1 1.1-1.1 1.2h-8.3zM27.3 52.3h6.6l1.1 1.1-1.1 1.1h-6.6z"/>
<path d="M55.4 47.2h3.7v1.3h-3.7zM83.7 49.7h2.8M114.7 54.6h3.7v1.3h-3.7zM124.5 49.7h2.8M131.9 49.7h2.8M139.3 49.7h2.8M24.9 79.2h9l1.1 1.1-1.1 1.1h-9zM26.9 68.1h7l1.1 1.1-1.1 1.1h-7zM26.9 70.8h7l1.1 1.2-1.1 1.1h-7zM26.9 73.6h7l1.1 1.1-1.1 1.2h-7zM26.9 76.4h7l1.1 1.1-1.1 1.1h-7zM272.3 60.8l1.2-1.1h8.7v2.3h-8.7z"/>
<path d="M272.3 63.6l1.2-1.1h8.7v2.2h-8.7zM272.3 66.4l1.2-1.1h8.7v2.2h-8.7zM272.3 69.2l1.2-1.1h8.7v2.2h-8.7zM272.3 73.8l1.2-1.1h9.2v2.2h-9.2zM272.3 76.6l1.2-1.1h9.2v2.2h-9.2zM272.3 79.4l1.2-1.1h9.2v2.2h-9.2zM27.6 82h6.3l1.1 1.1-1.1 1.1h-6.3zM27.9 84.8h6l1.1 1.1-1.1 1.1h-6zM27.9 87.5h6l1.1 1.1-1.1 1.2h-6zM27.9 90.3h6l1.1 1.1-1.1 1.1h-6zM27.9 93.1h6l1.1 1.1-1.1 1.1h-6zM27.9 95.9h6l1.1 1.1-1.1 1.1h-6z"/>
<path d="M29.7 98.7h4.2l1.1 1.1-1.1 1.1h-4.2zM115.7 97.4h3.7v1.1h-3.7zM115.7 99.2h3.7v1.1h-3.7zM180.6 97.4h3.7v1.1h-3.7zM180.6 99.2h3.7v1.1h-3.7zM239.9 97.4h3.7v1.1h-3.7zM239.9 99.2h3.7v1.1h-3.7zM272.3 97l1.2-1.1h5.6v2.2h-5.6zM272.3 99.8l1.2-1.1h5.4v2.2h-5.4zM272.3 84l1.2-1.1h7.4v2.2h-7.4zM272.3 86.8l1.2-1.1h7.4v2.2h-7.4zM272.3 89.6l1.2-1.1h7.4v2.2h-7.4z"/>
<path d="M272.3 92.4l1.2-1.2h7.4v2.3h-7.4zM15.2 119.4h2.4l.8 .8-.8 .7h-2.4zM18.2 115.3h12.9l1.1 1.2-1.1 1.1h-12.9zM19.5 119.4h1.8l.8 .8-.8 .7h-1.8zM23 104.2h10.9l1.1 1.1-1.1 1.1h-10.9zM24.5 119h6.6l1.1 1.2-1.1 1.1h-6.6zM29.4 101.4h4.5l1.1 1.2-1.1 1.1h-4.5zM57.3 108.4h3.7v1.3h-3.7zM115.7 101.1h3.7v1.1h-3.7zM115.7 102.9h3.7v1.1h-3.7zM123.1 104.8h3.7v1.1h-3.7zM123.1 106.6h3.7v1.1h-3.7z"/>
<path d="M123.1 108.5h3.7v1.1h-3.7zM123.1 110.3h3.7v1.1h-3.7zM180.6 101.1h3.7v1.1h-3.7zM180.6 102.9h3.7v1.1h-3.7zM188 104.8h3.7v1.1h-3.7zM188 106.6h3.7v1.1h-3.7zM188 108.5h3.7v1.1h-3.7zM188 110.3h3.7v1.1h-3.7zM239.9 101.1h3.7v1.1h-3.7zM239.9 102.9h3.7v1.1h-3.7zM246.4 104.8h3.7v1.1h-3.7zM246.4 106.6h3.7v1.1h-3.7z"/>
<path d="M246.4 108.5h3.7v1.1h-3.7zM246.4 110.3h3.7v1.1h-3.7zM272.3 114.6l1.2-1.1h8.3v2.2h-8.3zM273.5 110.7h7.8v2.2h-7.8l-1.2-1.1zM273.5 106.1h4.9v2.2h-4.9l-1.2-1.1zM273.5 103.3h4.9v2.2h-4.9l-1.2-1.1zM273.5 116.3h8v2.2h-8l-1.2-1.1zM50.3 127.6h2.8M115.2 138.7h2.8M115.7 127.1l.9-1.4 .9 1.4M124.5 138.7h2.8M124.9 127.1l1-1.4 .9 1.4"/>
<path d="M180.1 138.7h2.8M180.6 127.1l.9-1.4 .9 1.4M194.9 138.7h2.8M195.4 127.1l.9-1.4 1 1.4M239.4 138.7h2.8M239.9 127.1l.9-1.4 .9 1.4M246.8 138.7h2.8M247.3 127.1l.9-1.4 1 1.4M272.3 128.5l1.2-1.1h6.4v2.2h-6.4zM272.3 136.8l1.2-1.1h6.4v2.3h-6.4zM272.3 131.3l1.2-1.1h4v2.2h-4zM272.3 134.1l1.2-1.2h3.4v2.3h-3.4z"/>
<path d="M272.3 122.9l1.2-1.1h6v2.3h-6zM41 155.4h2.8M41.5 143.8l.9-1.4 1 1.4M86 141.9l.9-1.4 1 1.4M89.3 149.8h2.7M152.3 149.8h2.8M215.3 149.8h2.8M272.3 142.4l1.2-1.1h6v2.2h-6zM272.3 146.1l1.2-1.1h6v2.2h-6zM224.1 178.6h63.1M224.1 182.3h63.1M224.1 186h63.1"/>
<path d="M224.1 189.7h63.1M266.8 186v3.7M287.2 192.5v.9h-63.1"/>
</g>
<path d="M10 12.6h277.2v184.5h-277.2zM90.6 27.5h11.2v20.4h-11.2zM46.1 44.2a3.7 3.7 0 0 1 3.8 3.7 3.7 3.7 0 0 1-3.8 3.7zM101.8 51.6a3.7 3.7 0 0 1 3.7 3.7 3.7 3.7 0 0 1-3.7 3.7zM99.9 96.1h11.1v44.4h-11.1zM164.8 96.1h11.1v44.4h-11.1zM224.1 96.1h11.1v44.4h-11.1zM40.6 114.6a3.7 3.7 0 0 1 3.7 3.7 3.7 3.7 0 0 1-3.7 3.7zM224.1 174.9v22.2M287.2 174.9h-85.3v22.2" fill="none" stroke="#000" stroke-width=".47"/>
<path d="M7.2 9.9h282.7v190h-282.7zM40.6 116.5h3.1M40.6 120.2h3.1" fill="none" stroke="#000" stroke-width=".23"/>
<g fill="#000" stroke="#000" stroke-width=".18">
<path d="M124.4 43.4h3v.4h-3zM124.4 42.7h3v.4h-3zM131.8 43.4h3v.4h-3zM131.8 42.7h3v.4h-3zM139.2 43.4h3v.4h-3zM139.2 42.7h3v.4h-3zM115.1 132.4h3v.4h-3zM115.1 131.7h3v.3h-3zM124.4 132.4h3v.4h-3zM124.4 131.7h3v.3h-3zM180 132.4h3v.4h-3zM180 131.7h3v.3h-3z"/>
<path d="M194.8 132.4h3v.4h-3zM194.8 131.7h3v.3h-3zM239.3 132.4h3v.4h-3zM239.3 131.7h3v.3h-3zM246.7 132.4h3v.4h-3zM246.7 131.7h3v.3h-3zM41 149.1h2.9v.4h-2.9zM41 148.3h2.9v.4h-2.9z"/>
</g>
<g fill="#000" stroke="#000" stroke-width=".18">
<path d="M58.2 112l.6-.2v1.9a.92 .92 0 0 1-.8-.6 .92 .92 0 0 1 .2-1.1z" fill-rule="evenodd"/>
<path d="M58.2 115.7l.6-.2v1.9a.94 .94 0 0 1-.8-.6 .94 .94 0 0 1 .2-1.1z" fill-rule="evenodd"/>
<path d="M59.4 111.8a.92 .92 0 0 1 .9 .9 .92 .92 0 0 1-.9 1z" fill-rule="evenodd"/>
<path d="M59.4 115.5a.93 .93 0 0 1 .9 1 .93 .93 0 0 1-.9 .9z" fill-rule="evenodd"/>
<path d="M58.2 119.5l.6-.3v1.9a.93 .93 0 0 1-.8-.6 .93 .93 0 0 1 .2-1z" fill-rule="evenodd"/>
<path d="M58.2 123.2l.6-.3v1.9a.93 .93 0 0 1-.8-.6 .93 .93 0 0 1 .2-1z" fill-rule="evenodd"/>
<path d="M58.2 130.6l.6-.2v1.8a.93 .93 0 0 1-.8-.6 .93 .93 0 0 1 .2-1z" fill-rule="evenodd"/>
<path d="M59.4 119.2a.93 .93 0 0 1 .9 1 .93 .93 0 0 1-.9 .9z" fill-rule="evenodd"/>
<path d="M59.4 122.9a.93 .93 0 0 1 .9 1 .93 .93 0 0 1-.9 .9z" fill-rule="evenodd"/>
<path d="M59.4 130.4a.92 .92 0 0 1 .9 .9 .92 .92 0 0 1-.9 .9z" fill-rule="evenodd"/>
<circle cx="67.5" cy="27.5" r=".38"/>
<circle cx="85.1" cy="34.9" r=".38"/>
<circle cx="85.1" cy="31.2" r=".38"/>
<circle cx="85.1" cy="33" r=".38"/>
<circle cx="40.6" cy="46" r=".38"/>
<circle cx="48" cy="40.4" r=".38"/>
<circle cx="66.5" cy="57.1" r=".38"/>
<circle cx="68.4" cy="42.3" r=".38"/>
<circle cx="68.4" cy="53.4" r=".38"/>
<circle cx="159.2" cy="99.8" r=".38"/>
<circle cx="161.1" cy="97.9" r=".38"/>
<circle cx="51.7" cy="116.5" r=".38"/>
<circle cx="68.4" cy="105.3" r=".38"/>
<circle cx="155.5" cy="103.5" r=".38"/>
<circle cx="157.4" cy="101.6" r=".38"/>
<circle cx="259.4" cy="110.9" r=".38"/>
<circle cx="33.2" cy="120.2" r=".38"/>
<circle cx="51.7" cy="120.2" r=".38"/>
<circle cx="51.7" cy="123.9" r=".38"/>
<circle cx="94.4" cy="144.3" r=".38"/>
<circle cx="155.5" cy="146.1" r=".38"/>
<circle cx="157.4" cy="144.3" r=".38"/>
<circle cx="205.6" cy="146.1" r=".38"/>
<circle cx="218.6" cy="146.1" r=".38"/>
</g>
<path d="M107.3 28h5.6v8.2h-5.6zM114.7 96.6h5.6v8.2h-5.6zM179.6 96.6h5.6v8.2h-5.6zM239 96.6h5.5v8.2h-5.5zM122.2 104h5.5v8.2h-5.5zM187 104h5.6v8.2h-5.6zM245.4 104h5.6v8.2h-5.6z" fill="none" stroke="#000" stroke-width=".32"/>
<path d="M72.1 71v64l1.9 1.8h7.4l1.8-1.8v-44.5l3.7-3.7h53.8l3.7 3.7M263.1 62.7v89l-3.7 3.7h-52l-3.7-3.7M140.7 99.8v53.7l1.9 1.9h57.4l3.7-3.7M144.4 90.5l3.7-3.7h55.6l3.7 3.7v38.9M144.4 90.5v38.9M203.7 99.8v51.9" fill="none" stroke="#000" stroke-width=".57"/>
<use href="#words"/>
</svg>
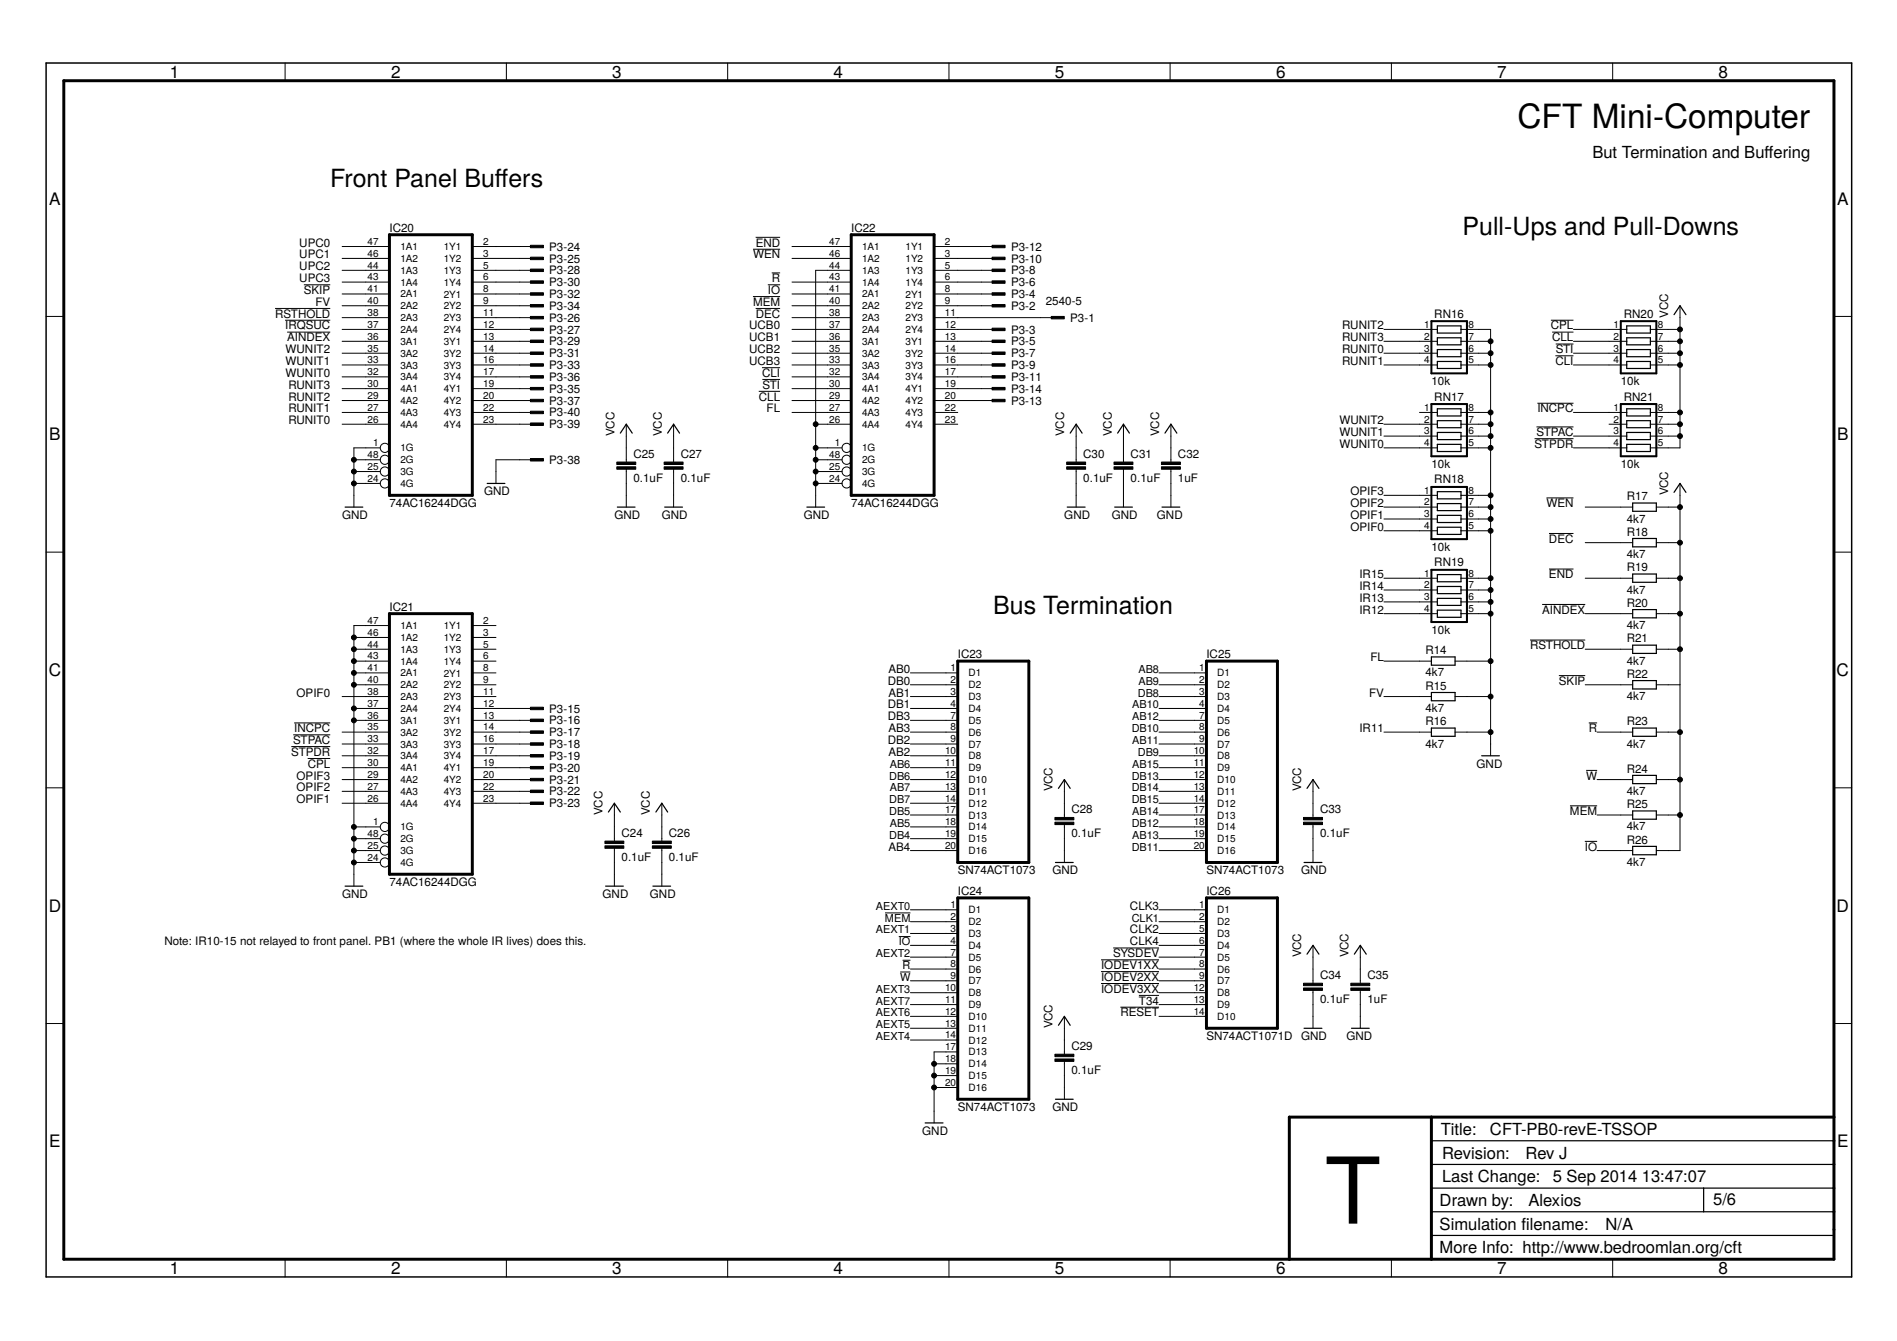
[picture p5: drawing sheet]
<svg xmlns="http://www.w3.org/2000/svg" width="297mm" height="210mm" viewBox="0 0 297 210" stroke-linecap="round" stroke-linejoin="round" font-family="sans-serif">
<defs><g id="words">
<text font-size="14.4" x="207.4" y="191.5">T</text>
<text font-size="5.2" x="237.6" y="20.1">CFT Mini-Computer</text>
<g font-size="3.9">
<text x="51.7" y="29.3">Front Panel Bufers</text>
<text x="77.5" y="29.3">f</text>
<text x="229" y="36.7">Pull-Ups and Pull-Downs</text>
<text x="155.5" y="96.1">Bus Termination</text>
</g>
<g font-size="2.7">
<text x="26.6" y="12.2">1</text>
<text x="61.2" y="12.2">2</text>
<text x="95.9" y="12.2">3</text>
<text x="130.5" y="12.2">4</text>
<text x="165.2" y="12.2">5</text>
<text x="199.8" y="12.2">6</text>
<text x="234.5" y="12.2">7</text>
<text x="269.1" y="12.2">8</text>
<text x="7.7" y="32">A</text>
<text x="287.7" y="32">A</text>
<text x="7.7" y="68.9">B</text>
<text x="287.7" y="68.9">B</text>
<text x="7.6" y="105.8">C</text>
<text x="287.6" y="105.8">C</text>
<text x="7.6" y="142.7">D</text>
<text x="287.6" y="142.7">D</text>
<text x="7.7" y="179.6">E</text>
<text x="287.7" y="179.6">E</text>
<text x="26.6" y="199.4">1</text>
<text x="61.2" y="199.4">2</text>
<text x="95.9" y="199.4">3</text>
<text x="130.5" y="199.4">4</text>
<text x="165.2" y="199.4">5</text>
<text x="199.8" y="199.4">6</text>
<text x="234.5" y="199.4">7</text>
<text x="269.1" y="199.4">8</text>
</g>
<g font-size="2.6">
<text x="249.3" y="24.7">But Termination and Bufering</text>
<text x="276.3" y="24.7">f</text>
<text x="225.6" y="177.6">Title:</text>
<text x="233.3" y="177.7">CFT-PB0-revE-TSSOP</text>
<text x="225.8" y="181.3">Revision:</text>
<text x="225.8" y="185">Last Change:</text>
<text x="238.9" y="181.4">Rev J</text>
<text x="243.1" y="185">5 Sep 2014</text>
<text x="257.1" y="185">13:47:07</text>
<text x="225.4" y="188.8">Drawn by:</text>
<text x="239.3" y="188.8">Alexios</text>
<text x="268.3" y="188.7">5/6</text>
<text x="225.4" y="192.5">Simulation flename:</text>
<text x="225.4" y="196.2">More Info: http://www.bedroomlan.org/cft</text>
<text x="238.2" y="192.5">i</text>
<text x="251.4" y="192.5">N/A</text>
</g>
<g font-size="1.8">
<text x="46.9" y="40.4">UPC1</text>
<text x="46.9" y="38.6">UPC0</text>
<text x="61" y="36.3">IC20</text>
<text x="86" y="39.2">P3-24</text>
<text x="86" y="41.1">P3-25</text>
<text x="117.9" y="40.4">WEN</text>
<text x="118.3" y="38.6">END</text>
<text x="133.3" y="36.3">IC22</text>
<text x="158.3" y="41.1">P3-10</text>
<text x="158.3" y="39.2">P3-12</text>
<text x="46.9" y="42.3">UPC2</text>
<text x="46.9" y="44.2">UPC3</text>
<text x="47.6" y="46">SKIP</text>
<text x="49.4" y="47.9">FV</text>
<text x="86" y="42.9">P3-28</text>
<text x="86" y="44.8">P3-30</text>
<text x="86" y="46.7">P3-32</text>
<text x="117.9" y="47.9">MEM</text>
<text x="120.2" y="46">IO</text>
<text x="120.8" y="44.2">R</text>
<text x="158.3" y="46.7">P3-4</text>
<text x="158.3" y="44.8">P3-6</text>
<text x="158.3" y="42.9">P3-8</text>
<text x="163.7" y="47.8">2540-5</text>
<text x="43.1" y="49.7">RSTHOLD</text>
<text x="44.6" y="51.6">IRQSUC</text>
<text x="45" y="53.4">AINDEX</text>
<text x="86" y="50.4">P3-26</text>
<text x="86" y="52.2">P3-27</text>
<text x="86" y="48.5">P3-34</text>
<text x="117.3" y="51.6">UCB0</text>
<text x="117.3" y="53.4">UCB1</text>
<text x="118.3" y="49.7">DEC</text>
<text x="158.3" y="48.5">P3-2</text>
<text x="158.3" y="52.2">P3-3</text>
<text x="167.6" y="50.4">P3-1</text>
<text x="210.2" y="51.6">RUNIT2</text>
<text x="210.2" y="53.4">RUNIT3</text>
<text x="224.6" y="49.7">RN16</text>
<text x="242.8" y="51.6">CPL</text>
<text x="243" y="53.4">CLL</text>
<text x="254.3" y="49.7">RN20</text>
<text x="261.2" y="49.7" transform="rotate(-90 261.2 49.7)">VCC</text>
<text x="44.7" y="59">WUNIT0</text>
<text x="44.7" y="57.1">WUNIT1</text>
<text x="44.7" y="55.3">WUNIT2</text>
<text x="86" y="54.1">P3-29</text>
<text x="86" y="55.9">P3-31</text>
<text x="86" y="57.8">P3-33</text>
<text x="86" y="59.6">P3-36</text>
<text x="117.3" y="55.3">UCB2</text>
<text x="117.3" y="57.1">UCB3</text>
<text x="119.3" y="59">CLI</text>
<text x="158.3" y="54.1">P3-5</text>
<text x="158.3" y="55.9">P3-7</text>
<text x="158.3" y="57.8">P3-9</text>
<text x="158.3" y="59.6">P3-11</text>
<text x="210.2" y="55.3">RUNIT0</text>
<text x="210.2" y="57.1">RUNIT1</text>
<text x="243.5" y="57.1">CLI</text>
<text x="243.6" y="55.3">STI</text>
<text x="45.2" y="62.7">RUNIT2</text>
<text x="45.2" y="60.8">RUNIT3</text>
<text x="45.2" y="64.5">RUNIT1</text>
<text x="86" y="61.5">P3-35</text>
<text x="86" y="63.3">P3-37</text>
<text x="86" y="65.2">P3-40</text>
<text x="118.8" y="62.7">CLL</text>
<text x="119.4" y="60.8">STI</text>
<text x="120" y="64.5">FL</text>
<text x="158.3" y="63.3">P3-13</text>
<text x="158.3" y="61.5">P3-14</text>
<text x="224.1" y="60.3">10k</text>
<text x="224.6" y="62.7">RN17</text>
<text x="240.7" y="64.5">INCPC</text>
<text x="253.8" y="60.3">10k</text>
<text x="254.3" y="62.7">RN21</text>
<text x="45.2" y="66.4">RUNIT0</text>
<text x="86" y="67">P3-39</text>
<text x="96.2" y="68.3" transform="rotate(-90 96.2 68.3)">VCC</text>
<text x="99.2" y="71.7">C25</text>
<text x="103.6" y="68.3" transform="rotate(-90 103.6 68.3)">VCC</text>
<text x="106.6" y="71.7">C27</text>
<text x="166.7" y="68.3" transform="rotate(-90 166.7 68.3)">VCC</text>
<text x="169.6" y="71.7">C30</text>
<text x="174.1" y="68.3" transform="rotate(-90 174.1 68.3)">VCC</text>
<text x="177" y="71.7">C31</text>
<text x="181.5" y="68.3" transform="rotate(-90 181.5 68.3)">VCC</text>
<text x="184.5" y="71.7">C32</text>
<text x="209.7" y="70.1">WUNIT0</text>
<text x="209.7" y="68.3">WUNIT1</text>
<text x="209.7" y="66.4">WUNIT2</text>
<text x="240.3" y="70.1">STPDR</text>
<text x="240.6" y="68.3">STPAC</text>
<text x="75.8" y="77.5">GND</text>
<text x="86" y="72.6">P3-38</text>
<text x="99.2" y="75.4">0.1uF</text>
<text x="106.6" y="75.4">0.1uF</text>
<text x="169.6" y="75.4">0.1uF</text>
<text x="177" y="75.4">0.1uF</text>
<text x="184.5" y="75.4">1uF</text>
<text x="211.4" y="77.5">OPIF3</text>
<text x="224.1" y="73.3">10k</text>
<text x="224.6" y="75.7">RN18</text>
<text x="253.8" y="73.3">10k</text>
<text x="261.2" y="77.5" transform="rotate(-90 261.2 77.5)">VCC</text>
<text x="53.6" y="81.2">GND</text>
<text x="61" y="79.4">74AC16244DGG</text>
<text x="96.2" y="81.2">GND</text>
<text x="103.6" y="81.2">GND</text>
<text x="125.9" y="81.2">GND</text>
<text x="133.3" y="79.4">74AC16244DGG</text>
<text x="166.7" y="81.2">GND</text>
<text x="174.1" y="81.2">GND</text>
<text x="181.2" y="81.2">GND</text>
<text x="211.4" y="83.1">OPIF0</text>
<text x="211.4" y="81.2">OPIF1</text>
<text x="211.4" y="79.4">OPIF2</text>
<text x="242.1" y="79.4">WEN</text>
<text x="254.7" y="81.8">4k7</text>
<text x="254.7" y="78.3">R17</text>
<text x="254.7" y="83.8">R18</text>
<text x="224.1" y="86.2">10k</text>
<text x="224.6" y="88.6">RN19</text>
<text x="242.5" y="84.9">DEC</text>
<text x="254.7" y="87.4">4k7</text>
<text x="254.7" y="89.4">R19</text>
<text x="61" y="95.6">IC21</text>
<text x="212.9" y="90.5">IR15</text>
<text x="212.9" y="94.2">IR13</text>
<text x="212.9" y="92.4">IR14</text>
<text x="242.5" y="90.5">END</text>
<text x="254.7" y="92.9">4k7</text>
<text x="254.7" y="95">R20</text>
<text x="212.9" y="96.1">IR12</text>
<text x="224.1" y="99.2">10k</text>
<text x="239.6" y="101.6">RSTHOLD</text>
<text x="241.5" y="96.1">AINDEX</text>
<text x="254.7" y="98.5">4k7</text>
<text x="254.7" y="100.5">R21</text>
<text x="139" y="107.2">DB0</text>
<text x="139.1" y="105.3">AB0</text>
<text x="150" y="103">IC23</text>
<text x="188.9" y="103">IC25</text>
<text x="214.6" y="103.5">FL</text>
<text x="223.2" y="105.9">4k7</text>
<text x="223.2" y="102.4">R14</text>
<text x="223.2" y="107.9">R15</text>
<text x="244.1" y="107.2">SKIP</text>
<text x="254.7" y="104">4k7</text>
<text x="254.7" y="106.1">R22</text>
<text x="46.4" y="109">OPIF0</text>
<text x="86" y="111.5">P3-15</text>
<text x="86" y="113.4">P3-16</text>
<text x="139" y="112.7">DB3</text>
<text x="139" y="110.9">DB1</text>
<text x="139.1" y="109">AB1</text>
<text x="214.4" y="109">FV</text>
<text x="223.2" y="111.4">4k7</text>
<text x="223.2" y="113.5">R16</text>
<text x="254.7" y="109.6">4k7</text>
<text x="254.7" y="113.5">R23</text>
<text x="45.6" y="118.3">STPDR</text>
<text x="45.9" y="116.5">STPAC</text>
<text x="46.1" y="114.6">INCPC</text>
<text x="86" y="115.2">P3-17</text>
<text x="86" y="117.1">P3-18</text>
<text x="86" y="119">P3-19</text>
<text x="139" y="116.5">DB2</text>
<text x="139.1" y="114.6">AB3</text>
<text x="139.1" y="118.3">AB2</text>
<text x="212.9" y="114.6">IR11</text>
<text x="223.2" y="117">4k7</text>
<text x="248.8" y="114.6">R</text>
<text x="254.7" y="117">4k7</text>
<text x="46.4" y="125.7">OPIF1</text>
<text x="46.4" y="123.9">OPIF2</text>
<text x="46.4" y="122">OPIF3</text>
<text x="48.2" y="120.2">CPL</text>
<text x="86" y="120.8">P3-20</text>
<text x="86" y="122.7">P3-21</text>
<text x="86" y="124.5">P3-22</text>
<text x="164.8" y="123.9" transform="rotate(-90 164.8 123.9)">VCC</text>
<text x="203.7" y="123.9" transform="rotate(-90 203.7 123.9)">VCC</text>
<text x="231.2" y="120.2">GND</text>
<text x="248.4" y="122">W</text>
<text x="254.7" y="124.4">4k7</text>
<text x="254.7" y="120.9">R24</text>
<text x="86" y="126.4">P3-23</text>
<text x="94.4" y="127.6" transform="rotate(-90 94.4 127.6)">VCC</text>
<text x="97.3" y="131">C24</text>
<text x="101.8" y="127.6" transform="rotate(-90 101.8 127.6)">VCC</text>
<text x="104.7" y="131">C26</text>
<text x="167.8" y="131">0.1uF</text>
<text x="167.8" y="127.3">C28</text>
<text x="206.7" y="131">0.1uF</text>
<text x="206.7" y="127.3">C33</text>
<text x="245.8" y="127.6">MEM</text>
<text x="254.7" y="130">4k7</text>
<text x="254.7" y="126.5">R25</text>
<text x="97.3" y="134.7">0.1uF</text>
<text x="104.7" y="134.7">0.1uF</text>
<text x="139.1" y="133.1">AB4</text>
<text x="150" y="136.8">SN74ACT1073</text>
<text x="164.8" y="136.8">GND</text>
<text x="188.9" y="136.8">SN74ACT1073</text>
<text x="203.7" y="136.8">GND</text>
<text x="248.2" y="133.1">IO</text>
<text x="254.7" y="135.5">4k7</text>
<text x="254.7" y="132">R26</text>
<text x="53.6" y="140.6">GND</text>
<text x="61" y="138.7">74AC16244DGG</text>
<text x="94.4" y="140.6">GND</text>
<text x="101.8" y="140.6">GND</text>
<text x="150" y="140.1">IC24</text>
<text x="176.9" y="142.4">CLK3</text>
<text x="188.9" y="140.1">IC26</text>
<text x="25.8" y="148">Note: IR10-15 not relayed to front panel. PB1 (where the whole IR lives) does this.</text>
<text x="174.3" y="149.8">SYSDEV</text>
<text x="176.9" y="146.1">CLK2</text>
<text x="176.9" y="148">CLK4</text>
<text x="203.7" y="149.8" transform="rotate(-90 203.7 149.8)">VCC</text>
<text x="211.2" y="149.8" transform="rotate(-90 211.2 149.8)">VCC</text>
<text x="172.4" y="155.4">IODEV3XX</text>
<text x="172.4" y="153.5">IODEV2XX</text>
<text x="172.4" y="151.7">IODEV1XX</text>
<text x="206.7" y="153.3">C34</text>
<text x="214.1" y="153.3">C35</text>
<text x="164.8" y="160.9" transform="rotate(-90 164.8 160.9)">VCC</text>
<text x="175.4" y="159.1">RESET</text>
<text x="178.3" y="157.2">T34</text>
<text x="206.7" y="157">0.1uF</text>
<text x="214.1" y="157">1uF</text>
<text x="167.8" y="164.4">C29</text>
<text x="188.9" y="162.8">SN74ACT1071D</text>
<text x="203.7" y="162.8">GND</text>
<text x="210.8" y="162.8">GND</text>
<text x="150" y="173.9">SN74ACT1073</text>
<text x="164.8" y="173.9">GND</text>
<text x="167.8" y="168.1">0.1uF</text>
<text x="144.4" y="177.6">GND</text>
</g>
<g font-size="1.7">
<text x="178.2" y="107.2">AB9</text>
<text x="178.2" y="105.3">AB8</text>
<text x="177.3" y="112.7">AB12</text>
<text x="177.3" y="110.9">AB10</text>
<text x="178.2" y="109">DB8</text>
<text x="177.2" y="114.6">DB10</text>
<text x="177.3" y="116.5">AB11</text>
<text x="178.2" y="118.3">DB9</text>
<text x="139.2" y="125.7">DB7</text>
<text x="139.2" y="122">DB6</text>
<text x="139.3" y="123.9">AB7</text>
<text x="139.3" y="120.2">AB6</text>
<text x="177.2" y="125.7">DB15</text>
<text x="177.2" y="123.9">DB14</text>
<text x="177.2" y="122">DB13</text>
<text x="177.3" y="120.2">AB15</text>
<text x="139.2" y="127.6">DB5</text>
<text x="139.2" y="131.3">DB4</text>
<text x="139.3" y="129.4">AB5</text>
<text x="177.2" y="129.4">DB12</text>
<text x="177.3" y="127.6">AB14</text>
<text x="177.3" y="131.3">AB13</text>
<text x="177.2" y="133.1">DB11</text>
<text x="137.1" y="142.4">AEXT0</text>
<text x="137.1" y="149.8">AEXT2</text>
<text x="137.1" y="146.1">AEXT1</text>
<text x="138.6" y="144.3">MEM</text>
<text x="140.7" y="148">IO</text>
<text x="177.2" y="144.3">CLK1</text>
<text x="137.1" y="155.4">AEXT3</text>
<text x="140.9" y="153.5">W</text>
<text x="141.3" y="151.7">R</text>
<text x="137.1" y="157.2">AEXT7</text>
<text x="137.1" y="159.1">AEXT6</text>
<text x="137.1" y="160.9">AEXT5</text>
<text x="137.1" y="162.8">AEXT4</text>
</g>
<g font-size="1.6">
<text x="57.5" y="38.3">47</text>
<text x="57.5" y="40.2">46</text>
<text x="62.7" y="39.2">1A1</text>
<text x="62.7" y="41">1A2</text>
<text x="69.5" y="39.2">1Y1</text>
<text x="69.5" y="41">1Y2</text>
<text x="75.7" y="38.3">2</text>
<text x="75.7" y="40.2">3</text>
<text x="129.8" y="38.3">47</text>
<text x="129.8" y="40.2">46</text>
<text x="135" y="39.2">1A1</text>
<text x="135" y="41">1A2</text>
<text x="141.8" y="39.2">1Y1</text>
<text x="141.8" y="41">1Y2</text>
<text x="148" y="38.3">2</text>
<text x="148" y="40.2">3</text>
<text x="57.5" y="42">44</text>
<text x="57.5" y="43.9">43</text>
<text x="57.5" y="45.8">41</text>
<text x="57.5" y="47.6">40</text>
<text x="62.7" y="42.9">1A3</text>
<text x="62.7" y="44.7">1A4</text>
<text x="62.7" y="46.6">2A1</text>
<text x="69.5" y="42.9">1Y3</text>
<text x="69.5" y="44.7">1Y4</text>
<text x="69.5" y="46.6">2Y1</text>
<text x="75.7" y="42">5</text>
<text x="75.7" y="43.9">6</text>
<text x="75.7" y="45.8">8</text>
<text x="75.7" y="47.6">9</text>
<text x="129.8" y="42">44</text>
<text x="129.8" y="43.9">43</text>
<text x="129.8" y="45.8">41</text>
<text x="129.8" y="47.6">40</text>
<text x="135" y="42.9">1A3</text>
<text x="135" y="44.7">1A4</text>
<text x="135" y="46.6">2A1</text>
<text x="141.8" y="42.9">1Y3</text>
<text x="141.8" y="44.7">1Y4</text>
<text x="141.8" y="46.6">2Y1</text>
<text x="148" y="42">5</text>
<text x="148" y="43.9">6</text>
<text x="148" y="45.8">8</text>
<text x="148" y="47.6">9</text>
<text x="57.5" y="49.5">38</text>
<text x="57.5" y="51.3">37</text>
<text x="57.5" y="53.2">36</text>
<text x="62.7" y="48.4">2A2</text>
<text x="62.7" y="50.3">2A3</text>
<text x="62.7" y="52.1">2A4</text>
<text x="62.7" y="54">3A1</text>
<text x="69.5" y="48.4">2Y2</text>
<text x="69.5" y="50.3">2Y3</text>
<text x="69.5" y="52.1">2Y4</text>
<text x="69.5" y="54">3Y1</text>
<text x="75.7" y="49.5">11</text>
<text x="75.7" y="51.3">12</text>
<text x="75.7" y="53.2">13</text>
<text x="129.8" y="49.5">38</text>
<text x="129.8" y="51.3">37</text>
<text x="129.8" y="53.2">36</text>
<text x="135" y="48.4">2A2</text>
<text x="135" y="50.3">2A3</text>
<text x="135" y="52.1">2A4</text>
<text x="135" y="54">3A1</text>
<text x="141.8" y="48.4">2Y2</text>
<text x="141.8" y="50.3">2Y3</text>
<text x="141.8" y="52.1">2Y4</text>
<text x="141.8" y="54">3Y1</text>
<text x="148" y="49.5">11</text>
<text x="148" y="51.3">12</text>
<text x="148" y="53.2">13</text>
<text x="223" y="53.2">2</text>
<text x="223" y="51.3">1</text>
<text x="230" y="53.2">7</text>
<text x="230" y="51.3">8</text>
<text x="252.7" y="53.2">2</text>
<text x="252.7" y="51.3">1</text>
<text x="259.6" y="53.2">7</text>
<text x="259.6" y="51.3">8</text>
<text x="57.5" y="55">35</text>
<text x="57.5" y="56.9">33</text>
<text x="57.5" y="58.7">32</text>
<text x="62.7" y="55.8">3A2</text>
<text x="62.7" y="57.7">3A3</text>
<text x="62.7" y="59.5">3A4</text>
<text x="69.5" y="55.8">3Y2</text>
<text x="69.5" y="57.7">3Y3</text>
<text x="69.5" y="59.6">3Y4</text>
<text x="75.7" y="55">14</text>
<text x="75.7" y="56.9">16</text>
<text x="75.7" y="58.7">17</text>
<text x="129.8" y="55">35</text>
<text x="129.8" y="56.9">33</text>
<text x="129.8" y="58.7">32</text>
<text x="135" y="55.8">3A2</text>
<text x="135" y="57.7">3A3</text>
<text x="135" y="59.5">3A4</text>
<text x="141.8" y="55.8">3Y2</text>
<text x="141.8" y="57.7">3Y3</text>
<text x="141.8" y="59.6">3Y4</text>
<text x="148" y="55">14</text>
<text x="148" y="56.9">16</text>
<text x="148" y="58.7">17</text>
<text x="223" y="55">3</text>
<text x="223" y="56.9">4</text>
<text x="230" y="56.9">5</text>
<text x="230" y="55">6</text>
<text x="252.7" y="55">3</text>
<text x="252.7" y="56.9">4</text>
<text x="259.6" y="56.9">5</text>
<text x="259.6" y="55">6</text>
<text x="57.5" y="60.6">30</text>
<text x="57.5" y="62.4">29</text>
<text x="57.5" y="64.3">27</text>
<text x="62.7" y="61.4">4A1</text>
<text x="62.7" y="63.3">4A2</text>
<text x="62.7" y="65.1">4A3</text>
<text x="69.5" y="61.4">4Y1</text>
<text x="69.5" y="63.3">4Y2</text>
<text x="69.5" y="65.1">4Y3</text>
<text x="75.7" y="60.6">19</text>
<text x="75.7" y="62.4">20</text>
<text x="75.7" y="64.3">22</text>
<text x="129.8" y="60.6">30</text>
<text x="129.8" y="62.4">29</text>
<text x="129.8" y="64.3">27</text>
<text x="135" y="61.4">4A1</text>
<text x="135" y="63.3">4A2</text>
<text x="135" y="65.1">4A3</text>
<text x="141.8" y="61.4">4Y1</text>
<text x="141.8" y="63.3">4Y2</text>
<text x="141.8" y="65.1">4Y3</text>
<text x="148" y="60.6">19</text>
<text x="148" y="62.4">20</text>
<text x="148" y="64.3">22</text>
<text x="223" y="64.3">1</text>
<text x="230" y="64.3">8</text>
<text x="252.7" y="64.3">1</text>
<text x="259.6" y="64.3">8</text>
<text x="57.5" y="71.7">48</text>
<text x="57.5" y="66.1">26</text>
<text x="58.4" y="69.9">1</text>
<text x="62.7" y="70.7">1G</text>
<text x="62.7" y="67">4A4</text>
<text x="69.5" y="67">4Y4</text>
<text x="75.7" y="66.1">23</text>
<text x="129.8" y="71.7">48</text>
<text x="129.8" y="66.1">26</text>
<text x="130.7" y="69.9">1</text>
<text x="135" y="70.7">1G</text>
<text x="135" y="67">4A4</text>
<text x="141.8" y="67">4Y4</text>
<text x="148" y="66.1">23</text>
<text x="223" y="66.1">2</text>
<text x="223" y="68">3</text>
<text x="223" y="69.9">4</text>
<text x="230" y="69.9">5</text>
<text x="230" y="68">6</text>
<text x="230" y="66.1">7</text>
<text x="252.7" y="66.1">2</text>
<text x="252.7" y="68">3</text>
<text x="252.7" y="69.9">4</text>
<text x="259.6" y="69.9">5</text>
<text x="259.6" y="68">6</text>
<text x="259.6" y="66.1">7</text>
<text x="57.5" y="73.6">25</text>
<text x="57.5" y="75.4">24</text>
<text x="62.7" y="72.5">2G</text>
<text x="62.7" y="74.4">3G</text>
<text x="62.7" y="76.2">4G</text>
<text x="129.8" y="73.6">25</text>
<text x="129.8" y="75.4">24</text>
<text x="135" y="72.5">2G</text>
<text x="135" y="74.4">3G</text>
<text x="135" y="76.2">4G</text>
<text x="223" y="77.3">1</text>
<text x="230" y="77.3">8</text>
<text x="223" y="79.1">2</text>
<text x="223" y="81">3</text>
<text x="223" y="82.8">4</text>
<text x="230" y="82.8">5</text>
<text x="230" y="81">6</text>
<text x="230" y="79.1">7</text>
<text x="223" y="92.1">2</text>
<text x="223" y="93.9">3</text>
<text x="223" y="95.8">4</text>
<text x="223" y="90.2">1</text>
<text x="230" y="95.8">5</text>
<text x="230" y="93.9">6</text>
<text x="230" y="92.1">7</text>
<text x="230" y="90.2">8</text>
<text x="57.5" y="97.7">47</text>
<text x="57.5" y="99.5">46</text>
<text x="57.5" y="101.4">44</text>
<text x="62.7" y="98.5">1A1</text>
<text x="62.7" y="100.3">1A2</text>
<text x="69.5" y="98.5">1Y1</text>
<text x="69.5" y="100.3">1Y2</text>
<text x="75.7" y="97.7">2</text>
<text x="75.7" y="99.5">3</text>
<text x="75.7" y="101.4">5</text>
<text x="57.5" y="103.2">43</text>
<text x="57.5" y="105.1">41</text>
<text x="57.5" y="106.9">40</text>
<text x="62.7" y="102.2">1A3</text>
<text x="62.7" y="104">1A4</text>
<text x="62.7" y="105.9">2A1</text>
<text x="62.7" y="107.7">2A2</text>
<text x="69.5" y="102.2">1Y3</text>
<text x="69.5" y="104">1Y4</text>
<text x="69.5" y="105.9">2Y1</text>
<text x="69.5" y="107.8">2Y2</text>
<text x="75.7" y="103.2">6</text>
<text x="75.7" y="105.1">8</text>
<text x="75.7" y="106.9">9</text>
<text x="148.8" y="105.1">1</text>
<text x="148.8" y="106.9">2</text>
<text x="151.7" y="105.9">D1</text>
<text x="151.7" y="107.7">D2</text>
<text x="187.8" y="105.1">1</text>
<text x="187.8" y="106.9">2</text>
<text x="190.6" y="105.9">D1</text>
<text x="190.6" y="107.7">D2</text>
<text x="57.5" y="108.8">38</text>
<text x="57.5" y="110.6">37</text>
<text x="57.5" y="112.5">36</text>
<text x="62.7" y="109.6">2A3</text>
<text x="62.7" y="111.4">2A4</text>
<text x="62.7" y="113.3">3A1</text>
<text x="69.5" y="109.6">2Y3</text>
<text x="69.5" y="111.5">2Y4</text>
<text x="69.5" y="113.3">3Y1</text>
<text x="75.7" y="108.8">11</text>
<text x="75.7" y="110.6">12</text>
<text x="75.7" y="112.5">13</text>
<text x="148.8" y="108.8">3</text>
<text x="148.8" y="110.6">4</text>
<text x="148.8" y="112.5">7</text>
<text x="151.7" y="109.6">D3</text>
<text x="151.7" y="111.4">D4</text>
<text x="151.7" y="113.3">D5</text>
<text x="187.8" y="108.8">3</text>
<text x="187.8" y="110.6">4</text>
<text x="187.8" y="112.5">7</text>
<text x="190.6" y="109.6">D3</text>
<text x="190.6" y="111.4">D4</text>
<text x="190.6" y="113.3">D5</text>
<text x="57.5" y="114.3">35</text>
<text x="57.5" y="116.2">33</text>
<text x="57.5" y="118">32</text>
<text x="57.5" y="119.9">30</text>
<text x="62.7" y="115.2">3A2</text>
<text x="62.7" y="117">3A3</text>
<text x="62.7" y="118.9">3A4</text>
<text x="69.5" y="115.2">3Y2</text>
<text x="69.5" y="117">3Y3</text>
<text x="69.5" y="118.9">3Y4</text>
<text x="75.7" y="114.3">14</text>
<text x="75.7" y="116.2">16</text>
<text x="75.7" y="118">17</text>
<text x="75.7" y="119.9">19</text>
<text x="148" y="118">10</text>
<text x="148" y="119.9">11</text>
<text x="148.8" y="114.3">8</text>
<text x="148.8" y="116.2">9</text>
<text x="151.7" y="115.2">D6</text>
<text x="151.7" y="117">D7</text>
<text x="151.7" y="118.9">D8</text>
<text x="186.9" y="118">10</text>
<text x="186.9" y="119.9">11</text>
<text x="187.8" y="114.3">8</text>
<text x="187.8" y="116.2">9</text>
<text x="190.6" y="115.2">D6</text>
<text x="190.6" y="117">D7</text>
<text x="190.6" y="118.9">D8</text>
<text x="57.5" y="121.8">29</text>
<text x="57.5" y="123.6">27</text>
<text x="57.5" y="125.5">26</text>
<text x="62.7" y="120.7">4A1</text>
<text x="62.7" y="122.6">4A2</text>
<text x="62.7" y="124.4">4A3</text>
<text x="69.5" y="120.7">4Y1</text>
<text x="69.5" y="122.6">4Y2</text>
<text x="69.5" y="124.4">4Y3</text>
<text x="75.7" y="121.8">20</text>
<text x="75.7" y="123.6">22</text>
<text x="75.7" y="125.5">23</text>
<text x="148" y="121.8">12</text>
<text x="148" y="123.6">13</text>
<text x="148" y="125.5">14</text>
<text x="151.7" y="120.7">D9</text>
<text x="151.7" y="122.6">D10</text>
<text x="151.7" y="124.4">D11</text>
<text x="186.9" y="121.8">12</text>
<text x="186.9" y="123.6">13</text>
<text x="186.9" y="125.5">14</text>
<text x="190.6" y="120.7">D9</text>
<text x="190.6" y="122.6">D10</text>
<text x="190.6" y="124.4">D11</text>
<text x="57.5" y="131">48</text>
<text x="58.4" y="129.2">1</text>
<text x="62.7" y="130">1G</text>
<text x="62.7" y="131.8">2G</text>
<text x="62.7" y="126.3">4A4</text>
<text x="69.5" y="126.3">4Y4</text>
<text x="148" y="127.3">17</text>
<text x="148" y="129.2">18</text>
<text x="148" y="131">19</text>
<text x="151.7" y="126.3">D12</text>
<text x="151.7" y="128.1">D13</text>
<text x="151.7" y="130">D14</text>
<text x="151.7" y="131.8">D15</text>
<text x="186.9" y="127.3">17</text>
<text x="186.9" y="129.2">18</text>
<text x="186.9" y="131">19</text>
<text x="190.6" y="126.3">D12</text>
<text x="190.6" y="128.1">D13</text>
<text x="190.6" y="130">D14</text>
<text x="190.6" y="131.8">D15</text>
<text x="57.5" y="132.9">25</text>
<text x="57.5" y="134.7">24</text>
<text x="62.7" y="133.7">3G</text>
<text x="62.7" y="135.5">4G</text>
<text x="148" y="132.9">20</text>
<text x="151.7" y="133.7">D16</text>
<text x="186.9" y="132.9">20</text>
<text x="190.6" y="133.7">D16</text>
<text x="148.8" y="142.1">1</text>
<text x="151.7" y="143">D1</text>
<text x="187.8" y="142.1">1</text>
<text x="190.6" y="143">D1</text>
<text x="148.8" y="144">2</text>
<text x="148.8" y="145.9">3</text>
<text x="148.8" y="147.7">4</text>
<text x="148.8" y="149.6">7</text>
<text x="151.7" y="144.8">D2</text>
<text x="151.7" y="146.7">D3</text>
<text x="151.7" y="148.5">D4</text>
<text x="187.8" y="144">2</text>
<text x="187.8" y="145.9">5</text>
<text x="187.8" y="147.7">6</text>
<text x="187.8" y="149.6">7</text>
<text x="190.6" y="144.8">D2</text>
<text x="190.6" y="146.7">D3</text>
<text x="190.6" y="148.5">D4</text>
<text x="148" y="155.1">10</text>
<text x="148.8" y="151.4">8</text>
<text x="148.8" y="153.3">9</text>
<text x="151.7" y="150.4">D5</text>
<text x="151.7" y="152.2">D6</text>
<text x="151.7" y="154.1">D7</text>
<text x="151.7" y="155.9">D8</text>
<text x="186.9" y="155.1">12</text>
<text x="187.8" y="151.4">8</text>
<text x="187.8" y="153.3">9</text>
<text x="190.6" y="150.4">D5</text>
<text x="190.6" y="152.2">D6</text>
<text x="190.6" y="154.1">D7</text>
<text x="190.6" y="155.9">D8</text>
<text x="148" y="157">11</text>
<text x="148" y="158.8">12</text>
<text x="148" y="160.7">13</text>
<text x="151.7" y="157.8">D9</text>
<text x="151.7" y="159.6">D10</text>
<text x="151.7" y="161.5">D11</text>
<text x="186.9" y="157">13</text>
<text x="186.9" y="158.8">14</text>
<text x="190.6" y="157.8">D9</text>
<text x="190.6" y="159.6">D10</text>
<text x="148" y="162.5">14</text>
<text x="148" y="164.4">17</text>
<text x="148" y="166.2">18</text>
<text x="151.7" y="163.4">D12</text>
<text x="151.7" y="165.2">D13</text>
<text x="151.7" y="167.1">D14</text>
<text x="148" y="168.1">19</text>
<text x="148" y="170">20</text>
<text x="151.7" y="168.9">D15</text>
<text x="151.7" y="170.8">D16</text>
</g>
</g></defs>
<g fill="none" stroke="#000" stroke-width=".16">
<path d="M10 12.6h277.2v184.5h-277.2zM44.6 9.9v2.7M79.3 9.9v2.7M113.9 9.9v2.7M148.6 9.9v2.7M183.2 9.9v2.7M217.9 9.9v2.7M252.5 9.9v2.7M53.6 38.6h7.4M74 38.6h9.2M117.9 39h4.3M118.3 37.1h3.9"/>
<path d="M124 38.6h9.3M146.3 38.6h9.2M7.2 49.5h2.8M43.1 48.3h8.6M44.6 50.1h7.1M45 52h6.7M47.6 44.6h4.1M53.6 40.4h7.4M53.6 42.3h7.4M53.6 44.2h7.4M53.6 46h7.4M53.6 47.9h7.4"/>
<path d="M53.6 49.7h7.4M53.6 51.6h7.4M53.6 53.4h7.4M53.6 55.3h7.4M53.6 57.1h7.4M53.6 59h7.4M74 40.4h9.2M74 42.3h9.2M74 44.2h9.2M74 46h9.2M74 47.9h9.2M74 49.7h9.2"/>
<path d="M74 51.6h9.2M74 53.4h9.2M74 55.3h9.2M74 57.1h9.2M74 59h9.2M117.9 46.4h4.3M118.3 48.3h3.9M119.3 57.6h2.9M119.4 59.4h2.8M120.2 44.6h2M120.8 42.7h1.4M124 40.4h9.3"/>
<path d="M124 44.2h9.3M124 46h9.3M124 47.9h9.3M124 49.7h9.3M124 51.6h9.3M124 53.4h9.3M124 55.3h9.3M124 57.1h9.3M124 59h9.3M133.3 42.3h-5.6v37.1M146.3 40.4h9.2M146.3 42.3h9.2"/>
<path d="M146.3 44.2h9.2M146.3 46h9.2M146.3 47.9h9.2M146.3 49.7h18.5M146.3 51.6h9.2M146.3 53.4h9.2M146.3 55.3h9.2M146.3 57.1h9.2M146.3 59h9.2M216.7 51.6h8.4M216.7 53.4h8.4M216.7 55.3h8.4"/>
<path d="M216.7 57.1h8.4M228.8 51.6h4.6v66.7M228.8 53.4h4.6M228.8 55.3h4.6M228.8 57.1h4.6M242.8 50.1h3.6M243 52h3.4M243.5 55.7h2.9M243.6 53.8h2.8M246.4 51.6h8.3M246.4 53.4h8.3M246.4 55.3h8.3"/>
<path d="M246.4 57.1h8.3M258.4 51.6h4.7M258.4 53.4h4.7M258.4 55.3h4.7M258.4 57.1h4.7M263.1 47.9v22.2h-4.7M287.2 49.5h2.7M53.6 60.8h7.4M53.6 62.7h7.4M53.6 64.6h7.4M53.6 66.4h7.4M55.4 72h4.1"/>
<path d="M55.4 73.8h4.1M55.4 75.7h4.1M59.5 70.1h-4.1v9.3M74 60.8h9.2M74 62.7h9.2M74 64.6h9.2M74 66.4h9.2M83.2 72h-5.5v3.7M98.1 66.4v5.9M98.1 73.4v6M105.5 66.4v5.9M105.5 73.4v6"/>
<path d="M118.8 61.3h3.4M124 60.8h9.3M124 62.7h9.3M124 64.6h9.3M127.7 70.1h4.1M127.7 72h4.1M127.7 73.8h4.1M127.7 75.7h4.1M127.7 66.4h5.6M146.3 60.8h9.2M146.3 62.7h9.2M146.3 64.6h3.7"/>
<path d="M146.3 66.4h3.7M168.5 66.4v5.9M168.5 73.4v6M175.9 66.4v5.9M175.9 73.4v6M183.3 66.4v5.9M183.3 73.4v6M216.7 70.1h8.4M216.7 66.4h8.4M216.7 77.5h8.4M216.7 79.4h8.4M216.7 68.3h8.4"/>
<path d="M222.3 64.6h2.8M228.8 70.1h4.6M228.8 64.6h4.6M228.8 66.4h4.6M228.8 77.5h4.6M228.8 79.4h4.6M228.8 68.3h4.6M240.3 68.7h6.1M240.6 66.8h5.8M240.7 63.1h5.7M242.1 77.9h4.3M246.4 70.1h8.3"/>
<path d="M246.4 64.6h8.3M246.4 68.3h8.3M248.2 79.4h7.5M251.9 66.4h2.8M258.4 64.6h4.7M258.4 66.4h4.7M258.4 68.3h4.7M259.4 79.4h3.7M263.1 75.7v57.4h-3.7M7.2 86.4h2.8M55.4 99.8h5.6M61 97.9h-5.6v40.8"/>
<path d="M74 97.9h3.7M74 99.8h3.7M216.7 81.2h8.4M216.7 83.1h8.4M216.7 90.5h8.4M216.7 92.4h8.4M216.7 94.2h8.4M216.7 96.1h8.4M228.8 81.2h4.6M228.8 83.1h4.6M228.8 90.5h4.6M228.8 92.4h4.6"/>
<path d="M228.8 94.2h4.6M228.8 96.1h4.6M241.5 94.6h6.7M242.5 89.1h3.9M242.5 83.5h3.9M248.2 84.9h7.5M248.2 90.5h7.5M248.2 96.1h7.5M259.4 84.9h3.7M259.4 90.5h3.7M259.4 96.1h3.7M287.2 86.4h2.7"/>
<path d="M45.6 116.9h6.1M45.9 115h5.8M46.1 113.2h5.6M48.2 118.7h3.5M53.6 109h7.4M53.6 114.6h7.4M53.6 116.5h7.4M53.6 118.3h7.4M55.4 101.6h5.6M55.4 103.5h5.6M55.4 105.3h5.6M55.4 107.2h5.6"/>
<path d="M55.4 110.9h5.6M55.4 112.8h5.6M74 101.6h3.7M74 103.5h3.7M74 105.3h3.7M74 107.2h3.7M74 109h3.7M74 110.9h9.2M74 112.8h9.2M74 114.6h9.2M74 116.5h9.2M74 118.3h9.2"/>
<path d="M142.6 105.3h7.4M142.6 107.2h7.4M142.6 109h7.4M142.6 110.9h7.4M142.6 112.8h7.4M142.6 114.6h7.4M142.6 116.5h7.4M142.6 118.3h7.4M181.5 105.3h7.4M181.5 107.2h7.4M181.5 109h7.4M181.5 110.9h7.4"/>
<path d="M181.5 112.8h7.4M181.5 114.6h7.4M181.5 116.5h7.4M181.5 118.3h7.4M216.7 103.5h7.4M216.7 109h7.4M216.7 114.6h7.4M227.8 103.5h5.6M227.8 109h5.6M227.8 114.6h5.6M239.6 100.2h8.6M244.1 105.7h4.1"/>
<path d="M248.2 101.6h7.5M248.2 107.2h7.5M248.8 113.2h1.3M250.1 114.6h5.6M259.4 101.6h3.7M259.4 107.2h3.7M259.4 114.6h3.7M7.2 123.3h2.8M53.6 120.2h7.4M53.6 122h7.4M53.6 123.9h7.4M53.6 125.7h7.4"/>
<path d="M55.4 129.4h4.1M55.4 131.3h4.1M55.4 133.1h4.1M55.4 135h4.1M74 120.2h9.2M74 122h9.2M74 123.9h9.2M74 125.7h9.2M96.2 125.7v6M96.2 132.8v5.9M103.6 125.7v6M103.6 132.8v5.9"/>
<path d="M142.6 129.4h7.4M142.6 131.3h7.4M142.6 133.1h7.4M142.6 120.2h7.4M142.6 122h7.4M142.6 123.9h7.4M142.6 125.7h7.4M142.6 127.6h7.4M166.7 122v6M166.7 129.1v5.9M181.5 129.4h7.4M181.5 131.3h7.4"/>
<path d="M181.5 133.1h7.4M181.5 120.2h7.4M181.5 122h7.4M181.5 123.9h7.4M181.5 125.7h7.4M181.5 127.6h7.4M205.6 122v6M205.6 129.1v5.9M245.8 126.1h4.3M248.2 131.7h1.9M248.4 120.6h1.7M250.1 133.1h5.6"/>
<path d="M250.1 122h5.6M250.1 127.6h5.6M259.4 122h3.7M259.4 127.6h3.7M287.2 123.3h2.7M138.6 142.9h4M140.7 146.6h1.9M140.9 152.1h1.7M141.3 150.3h1.3M142.6 142.4h7.4M142.6 144.3h7.4M142.6 146.1h7.4"/>
<path d="M142.6 148h7.4M142.6 149.8h7.4M142.6 151.7h7.4M142.6 153.5h7.4M142.6 155.4h7.4M142.6 157.2h7.4M142.6 159.1h7.4M166.7 159.1v5.9M172.4 153.9h9.1M172.4 152.1h9.1M172.4 150.2h9.1M174.3 148.4h7.2"/>
<path d="M175.4 157.6h6.1M178.3 155.8h3.2M181.5 142.4h7.4M181.5 144.3h7.4M181.5 146.1h7.4M181.5 148h7.4M181.5 149.8h7.4M181.5 151.7h7.4M181.5 153.5h7.4M181.5 155.4h7.4M181.5 157.2h7.4M181.5 159.1h7.4"/>
<path d="M205.6 148v5.9M205.6 155v6M213 148v5.9M213 155v6M7.2 160.2h2.8M142.6 161h7.4M142.6 162.8h7.4M146.3 166.5h3.7M146.3 168.4h3.7M146.3 170.2h3.7M150 164.7h-3.7v11.1M166.7 166.1v6"/>
<path d="M287.2 160.2h2.7M44.6 197.1v2.8M79.3 197.1v2.8M113.9 197.1v2.8M148.6 197.1v2.8M183.2 197.1v2.8M217.9 197.1v2.8M252.5 197.1v2.8M287.2 197h.1"/>
<circle cx="60.3" cy="73.8" r=".72"/>
<circle cx="60.3" cy="75.7" r=".72"/>
<circle cx="60.3" cy="72" r=".72"/>
<circle cx="60.3" cy="70.1" r=".72"/>
<circle cx="132.6" cy="73.8" r=".72"/>
<circle cx="132.6" cy="75.7" r=".72"/>
<circle cx="132.6" cy="70.1" r=".72"/>
<circle cx="132.6" cy="72" r=".72"/>
<circle cx="60.3" cy="133.1" r=".72"/>
<circle cx="60.3" cy="129.4" r=".72"/>
<circle cx="60.3" cy="135" r=".72"/>
<circle cx="60.3" cy="131.3" r=".72"/>
</g>
<path d="M10 12.6h277.2v184.5h-277.2zM61 36.7h13v40.8h-13zM133.3 36.7h13v40.8h-13zM61 96.1h13v40.7h-13zM150 103.5h11.1v31.5h-11.1zM188.9 103.5h11.1v31.5h-11.1zM150 140.5h11.1v31.6h-11.1zM188.9 140.5h11.1v20.5h-11.1zM224.1 174.9v22.2M287.2 174.9h-85.3v22.2" fill="none" stroke="#000" stroke-width=".47"/>
<g fill="none" stroke="#000" stroke-width=".19">
<path d="M225.1 51h3.7v1.1h-3.7zM225.1 52.9h3.7v1.1h-3.7zM225.1 54.7h3.7v1.1h-3.7zM225.1 56.6h3.7v1.1h-3.7zM254.7 51h3.7v1.1h-3.7zM254.7 52.9h3.7v1.1h-3.7zM254.7 54.7h3.7v1.1h-3.7zM254.7 56.6h3.7v1.1h-3.7zM262.1 49.3l1-1.4 .9 1.4M54 79.4h2.8M76.3 75.7h2.8M96.7 79.4h2.7"/>
<path d="M97.1 67.8l1-1.4 .9 1.4M104.1 79.4h2.8M104.5 67.8l1-1.4 .9 1.4M126.3 79.4h2.8M167.1 79.4h2.8M167.6 67.8l.9-1.4 .9 1.4M174.5 79.4h2.8M175 67.8l.9-1.4 .9 1.4M181.9 79.4h2.8M182.4 67.8l.9-1.4 1 1.4M225.1 64h3.7v1.1h-3.7zM225.1 65.8h3.7v1.2h-3.7z"/>
<path d="M225.1 67.7h3.7v1.1h-3.7zM225.1 69.6h3.7v1.1h-3.7zM225.1 77h3.7v1.1h-3.7zM225.1 78.8h3.7v1.1h-3.7zM254.7 64h3.7v1.1h-3.7zM254.7 65.8h3.7v1.2h-3.7zM254.7 67.7h3.7v1.1h-3.7zM254.7 69.6h3.7v1.1h-3.7zM255.7 78.7h3.7v1.3h-3.7zM262.1 77.1l1-1.4 .9 1.4M225.1 80.7h3.7v1.1h-3.7zM225.1 82.5h3.7v1.2h-3.7z"/>
<path d="M225.1 89.9h3.7v1.2h-3.7zM225.1 91.8h3.7v1.1h-3.7zM225.1 93.7h3.7v1.1h-3.7zM225.1 95.5h3.7v1.1h-3.7zM255.7 84.3h3.7v1.3h-3.7zM255.7 89.9h3.7v1.2h-3.7zM255.7 95.4h3.7v1.3h-3.7zM224.1 102.8h3.7v1.3h-3.7zM224.1 108.4h3.7v1.3h-3.7zM224.1 114h3.7v1.3h-3.7zM232 118.3h2.8M255.7 101h3.7v1.3h-3.7z"/>
<path d="M255.7 106.5h3.7v1.3h-3.7zM255.7 114h3.7v1.3h-3.7zM54 138.7h2.8M94.8 138.7h2.8M95.3 127.1l.9-1.4 .9 1.4M102.2 138.7h2.8M102.7 127.1l.9-1.4 .9 1.4M165.3 135h2.7M165.7 123.4l1-1.4 .9 1.4M204.2 135h2.8M204.7 123.4l.9-1.4 .9 1.4M255.7 121.4h3.7v1.3h-3.7z"/>
<path d="M255.7 126.9h3.7v1.3h-3.7zM255.7 132.5h3.7v1.3h-3.7zM204.7 149.4l.9-1.4 .9 1.4M212.1 149.4l.9-1.4 .9 1.4M144.9 175.8h2.8M165.3 172.1h2.7M165.7 160.5l1-1.4 .9 1.4M204.2 161h2.8M211.6 161h2.8M224.1 178.6h63.1M224.1 182.3h63.1M224.1 186h63.1"/>
<path d="M224.1 189.7h63.1M266.8 186v3.7M287.2 192.5v.9h-63.1"/>
</g>
<path d="M7.2 9.9h282.7v190h-282.7z" fill="none" stroke="#000" stroke-width=".23"/>
<g fill="#000" stroke="#000" stroke-width=".16">
<path d="M83.1 38.4h2v.4h-2zM155.3 38.4h2.1v.4h-2.1zM83.1 40.3h2v.3h-2zM83.1 49.5h2v.4h-2zM83.1 51.4h2v.4h-2zM83.1 42.1h2v.4h-2zM83.1 53.2h2v.4h-2zM83.1 44h2v.3h-2zM83.1 55.1h2v.4h-2zM83.1 45.8h2v.4h-2zM83.1 56.9h2v.4h-2zM83.1 47.7h2v.3h-2z"/>
<path d="M83.1 58.8h2v.4h-2zM155.3 47.7h2.1v.3h-2.1zM155.3 51.4h2.1v.4h-2.1zM155.3 45.8h2.1v.4h-2.1zM155.3 53.2h2.1v.4h-2.1zM155.3 44h2.1v.3h-2.1zM155.3 55.1h2.1v.4h-2.1zM155.3 42.1h2.1v.4h-2.1zM155.3 56.9h2.1v.4h-2.1zM155.3 40.3h2.1v.3h-2.1zM155.3 58.8h2.1v.4h-2.1zM164.6 49.5h2v.4h-2z"/>
<path d="M83.1 60.6h2v.4h-2zM83.1 62.5h2v.4h-2zM83.1 71.8h2v.4h-2zM83.1 66.2h2v.4h-2zM83.1 64.4h2v.3h-2zM96.6 73.1h2.9v.3h-2.9zM96.6 72.3h2.9v.4h-2.9zM104 73.1h3v.3h-3zM104 72.3h3v.4h-3zM155.3 62.5h2.1v.4h-2.1zM155.3 60.6h2.1v.4h-2.1zM167 73.1h3v.3h-3z"/>
<path d="M167 72.3h3v.4h-3zM174.4 73.1h3v.3h-3zM174.4 72.3h3v.4h-3zM181.9 73.1h2.9v.3h-2.9zM181.9 72.3h2.9v.4h-2.9zM83.1 110.7h2v.4h-2zM83.1 112.6h2v.3h-2zM83.1 114.4h2v.4h-2zM83.1 116.3h2v.3h-2zM83.1 118.1h2v.4h-2zM83.1 120h2v.4h-2zM83.1 121.8h2v.4h-2z"/>
<path d="M83.1 123.7h2v.4h-2zM83.1 125.5h2v.4h-2zM94.7 132.4h3v.4h-3zM94.7 131.7h3v.3h-3zM102.2 132.4h2.9v.4h-2.9zM102.2 131.7h2.9v.3h-2.9zM165.2 128.7h2.9v.4h-2.9zM165.2 128h2.9v.3h-2.9zM204.1 128.7h3v.4h-3zM204.1 128h3v.3h-3zM204.1 154.6h3v.4h-3zM204.1 153.9h3v.4h-3z"/>
<path d="M211.5 154.6h3v.4h-3zM211.5 153.9h3v.4h-3zM165.2 165.8h2.9v.3h-2.9zM165.2 165h2.9v.4h-2.9z"/>
</g>
<path d="M224.1 50.3h5.6v8.1h-5.6zM253.8 50.3h5.6v8.1h-5.6zM224.1 63.2h5.6v8.2h-5.6zM224.1 76.2h5.6v8.2h-5.6zM253.8 63.2h5.6v8.2h-5.6zM224.1 89.2h5.6v8.2h-5.6z" fill="none" stroke="#000" stroke-width=".32"/>
<g fill="#000" stroke="#000" stroke-width=".16">
<circle cx="233.4" cy="57.1" r=".38"/>
<circle cx="233.4" cy="55.3" r=".38"/>
<circle cx="233.4" cy="53.4" r=".38"/>
<circle cx="263.1" cy="51.6" r=".38"/>
<circle cx="263.1" cy="53.4" r=".38"/>
<circle cx="263.1" cy="55.3" r=".38"/>
<circle cx="263.1" cy="57.1" r=".38"/>
<circle cx="55.4" cy="75.7" r=".38"/>
<circle cx="55.4" cy="73.8" r=".38"/>
<circle cx="55.4" cy="72" r=".38"/>
<circle cx="127.7" cy="73.8" r=".38"/>
<circle cx="127.7" cy="66.4" r=".38"/>
<circle cx="127.7" cy="70.1" r=".38"/>
<circle cx="127.7" cy="72" r=".38"/>
<circle cx="127.7" cy="75.7" r=".38"/>
<circle cx="233.4" cy="68.3" r=".38"/>
<circle cx="233.4" cy="64.6" r=".38"/>
<circle cx="233.4" cy="79.4" r=".38"/>
<circle cx="233.4" cy="66.4" r=".38"/>
<circle cx="233.4" cy="70.1" r=".38"/>
<circle cx="233.4" cy="77.5" r=".38"/>
<circle cx="263.1" cy="79.4" r=".38"/>
<circle cx="263.1" cy="68.3" r=".38"/>
<circle cx="263.1" cy="66.4" r=".38"/>
<circle cx="263.1" cy="64.6" r=".38"/>
<circle cx="55.4" cy="99.8" r=".38"/>
<circle cx="233.4" cy="83.1" r=".38"/>
<circle cx="233.4" cy="81.2" r=".38"/>
<circle cx="233.4" cy="96.1" r=".38"/>
<circle cx="233.4" cy="94.2" r=".38"/>
<circle cx="233.4" cy="90.5" r=".38"/>
<circle cx="233.4" cy="92.4" r=".38"/>
<circle cx="263.1" cy="84.9" r=".38"/>
<circle cx="263.1" cy="90.5" r=".38"/>
<circle cx="263.1" cy="96.1" r=".38"/>
<circle cx="55.4" cy="112.8" r=".38"/>
<circle cx="55.4" cy="101.6" r=".38"/>
<circle cx="55.4" cy="105.3" r=".38"/>
<circle cx="55.4" cy="110.9" r=".38"/>
<circle cx="55.4" cy="103.5" r=".38"/>
<circle cx="55.4" cy="107.2" r=".38"/>
<circle cx="233.4" cy="114.6" r=".38"/>
<circle cx="233.4" cy="103.5" r=".38"/>
<circle cx="233.4" cy="109" r=".38"/>
<circle cx="263.1" cy="101.6" r=".38"/>
<circle cx="263.1" cy="114.6" r=".38"/>
<circle cx="55.4" cy="131.3" r=".38"/>
<circle cx="55.4" cy="135" r=".38"/>
<circle cx="55.4" cy="133.1" r=".38"/>
<circle cx="55.4" cy="129.4" r=".38"/>
<circle cx="263.1" cy="122" r=".38"/>
<circle cx="263.1" cy="127.6" r=".38"/>
<circle cx="146.3" cy="166.5" r=".38"/>
<circle cx="146.3" cy="168.4" r=".38"/>
<circle cx="146.3" cy="170.2" r=".38"/>
</g>
<use href="#words"/>
</svg>
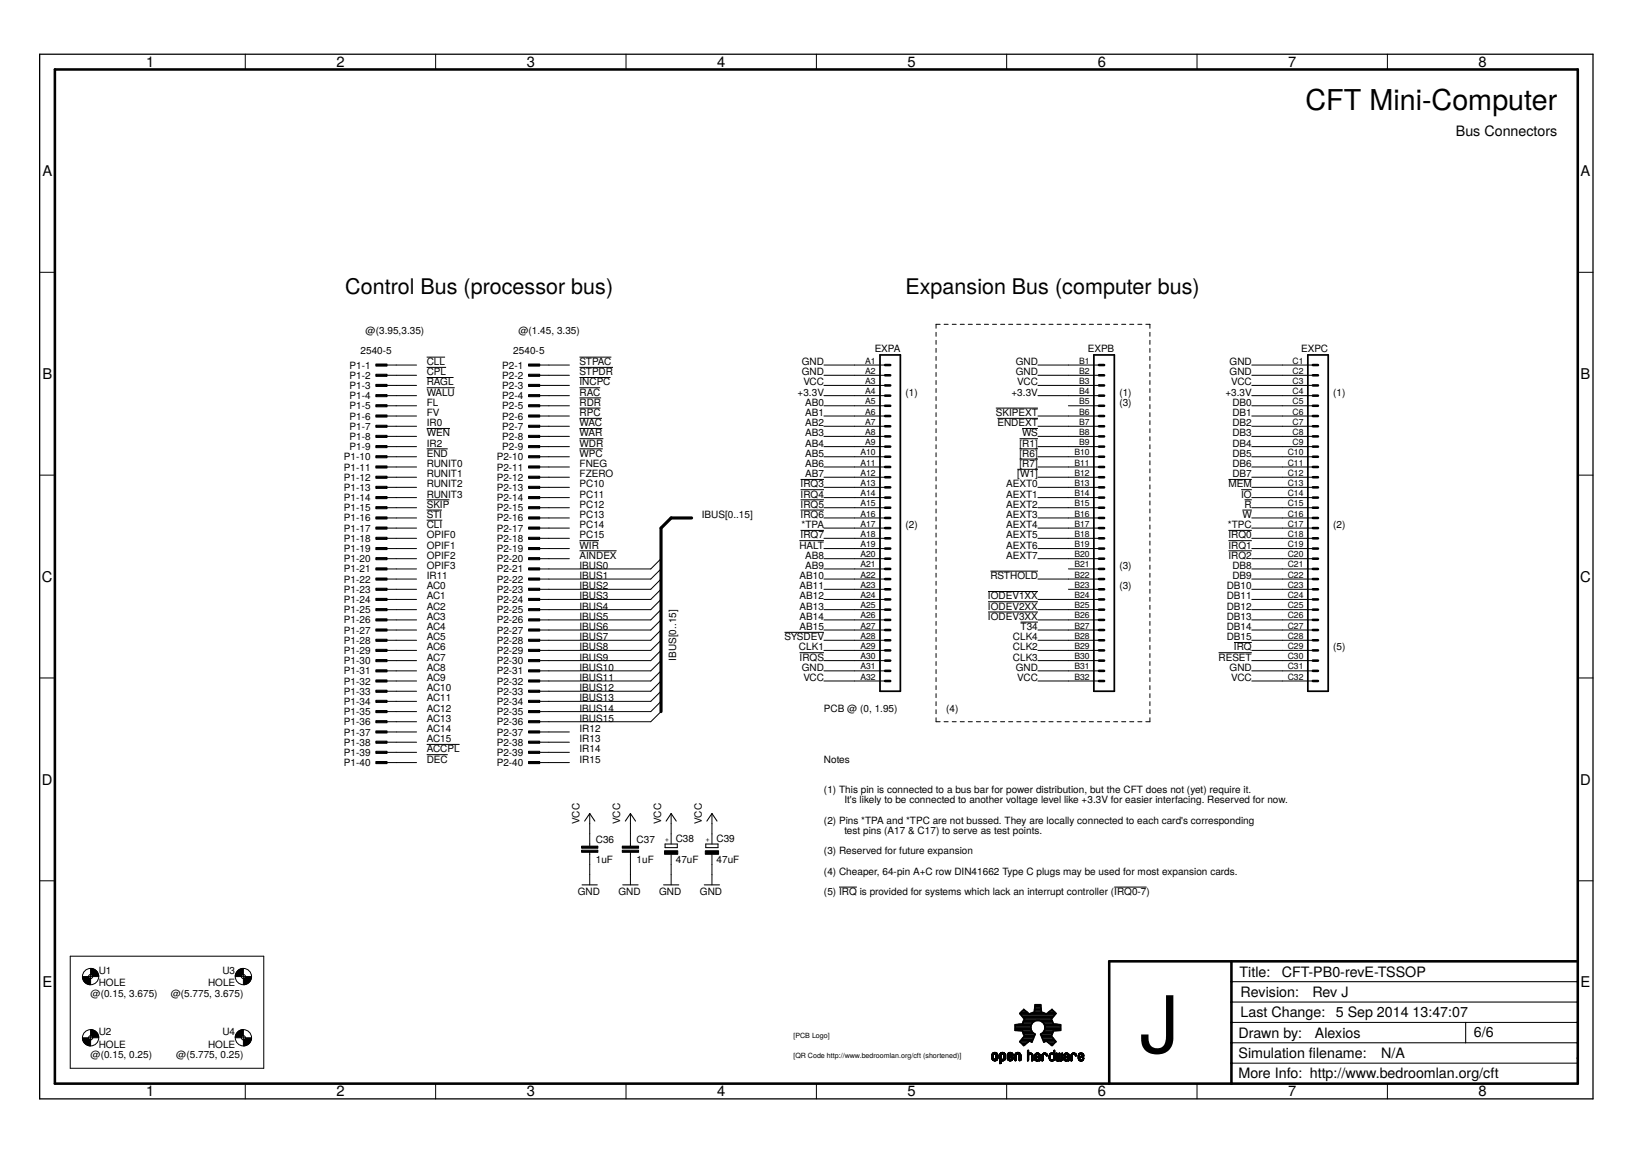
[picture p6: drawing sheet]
<svg xmlns="http://www.w3.org/2000/svg" width="297mm" height="210mm" viewBox="0 0 297 210" stroke-linecap="round" stroke-linejoin="round" font-family="sans-serif">
<defs><g id="words">
<text font-size="14.4" x="207.4" y="191.5">J</text>
<text font-size="5.2" x="237.6" y="20.1">CFT Mini-Computer</text>
<g font-size="3.9">
<text x="62.8" y="53.4">Control Bus (processor bus)</text>
<text x="164.8" y="53.4">Expansion Bus (computer bus)</text>
</g>
<g font-size="2.7">
<text x="26.6" y="12.2">1</text>
<text x="61.2" y="12.2">2</text>
<text x="95.9" y="12.2">3</text>
<text x="130.5" y="12.2">4</text>
<text x="165.2" y="12.2">5</text>
<text x="199.8" y="12.2">6</text>
<text x="234.5" y="12.2">7</text>
<text x="269.1" y="12.2">8</text>
<text x="7.7" y="32">A</text>
<text x="287.7" y="32">A</text>
<text x="7.7" y="68.9">B</text>
<text x="287.7" y="68.9">B</text>
<text x="7.6" y="105.8">C</text>
<text x="287.6" y="105.8">C</text>
<text x="7.6" y="142.7">D</text>
<text x="287.6" y="142.7">D</text>
<text x="7.7" y="179.6">E</text>
<text x="287.7" y="179.6">E</text>
<text x="26.6" y="199.4">1</text>
<text x="61.2" y="199.4">2</text>
<text x="95.9" y="199.4">3</text>
<text x="130.5" y="199.4">4</text>
<text x="165.2" y="199.4">5</text>
<text x="199.8" y="199.4">6</text>
<text x="234.5" y="199.4">7</text>
<text x="269.1" y="199.4">8</text>
</g>
<g font-size="2.6">
<text x="265" y="24.7">Bus Connectors</text>
<text x="225.6" y="177.6">Title:</text>
<text x="233.3" y="177.7">CFT-PB0-revE-TSSOP</text>
<text x="225.8" y="181.3">Revision:</text>
<text x="225.8" y="185">Last Change:</text>
<text x="238.9" y="181.4">Rev J</text>
<text x="243.1" y="185">5 Sep 2014</text>
<text x="257.1" y="185">13:47:07</text>
<text x="225.4" y="188.8">Drawn by:</text>
<text x="239.3" y="188.8">Alexios</text>
<text x="268.3" y="188.7">6/6</text>
<text x="225.4" y="192.5">Simulation flename:</text>
<text x="225.4" y="196.2">More Info: http://www.bedroomlan.org/cft</text>
<text x="238.2" y="192.5">i</text>
<text x="251.4" y="192.5">N/A</text>
</g>
<g font-size="1.8">
<text x="65.6" y="64.5">2540-5</text>
<text x="66.5" y="60.8">@(3.95,3.35)</text>
<text x="93.4" y="64.5">2540-5</text>
<text x="94.4" y="60.8">@(1.45, 3.35)</text>
<text x="159.2" y="64">EXPA</text>
<text x="198" y="64">EXPB</text>
<text x="236.8" y="64">EXPC</text>
<text x="63.6" y="67">P1-1</text>
<text x="63.6" y="68.9">P1-2</text>
<text x="63.6" y="70.8">P1-3</text>
<text x="77.7" y="66.4">CLL</text>
<text x="77.7" y="68.3">CPL</text>
<text x="77.7" y="72">WALU</text>
<text x="77.7" y="70.1">RAGL</text>
<text x="91.4" y="67">P2-1</text>
<text x="91.4" y="68.9">P2-2</text>
<text x="91.4" y="70.8">P2-3</text>
<text x="105.5" y="68.3">STPDR</text>
<text x="105.5" y="70.1">INCPC</text>
<text x="105.5" y="66.4">STPAC</text>
<text x="105.5" y="72">RAC</text>
<text x="145.2" y="72">+3.3V</text>
<text x="145.9" y="68.3">GND</text>
<text x="145.9" y="66.4">GND</text>
<text x="146.2" y="70.1">VCC</text>
<text x="164.8" y="72">(1)</text>
<text x="184.1" y="72">+3.3V</text>
<text x="184.9" y="68.3">GND</text>
<text x="184.9" y="66.4">GND</text>
<text x="185.2" y="70.1">VCC</text>
<text x="203.7" y="72">(1)</text>
<text x="223" y="72">+3.3V</text>
<text x="223.8" y="68.3">GND</text>
<text x="223.8" y="66.4">GND</text>
<text x="224.1" y="70.1">VCC</text>
<text x="242.7" y="72">(1)</text>
<text x="63.6" y="72.6">P1-4</text>
<text x="63.6" y="74.5">P1-5</text>
<text x="63.6" y="76.3">P1-6</text>
<text x="77.7" y="75.7">FV</text>
<text x="77.7" y="73.8">FL</text>
<text x="77.7" y="77.5">IR0</text>
<text x="91.4" y="72.6">P2-4</text>
<text x="91.4" y="74.5">P2-5</text>
<text x="91.4" y="76.3">P2-6</text>
<text x="105.5" y="75.7">RPC</text>
<text x="105.5" y="73.8">RDR</text>
<text x="105.5" y="77.5">WAC</text>
<text x="146.5" y="77.5">AB2</text>
<text x="146.5" y="75.7">AB1</text>
<text x="146.5" y="73.8">AB0</text>
<text x="181.2" y="75.7">SKIPEXT</text>
<text x="181.5" y="77.5">ENDEXT</text>
<text x="203.7" y="73.8">(3)</text>
<text x="224.3" y="77.5">DB2</text>
<text x="224.3" y="75.7">DB1</text>
<text x="224.3" y="73.8">DB0</text>
<text x="62.6" y="83.7">P1-10</text>
<text x="63.6" y="78.2">P1-7</text>
<text x="63.6" y="80">P1-8</text>
<text x="63.6" y="81.9">P1-9</text>
<text x="77.7" y="81.2">IR2</text>
<text x="77.7" y="79.4">WEN</text>
<text x="77.7" y="83.1">END</text>
<text x="90.4" y="83.7">P2-10</text>
<text x="91.4" y="78.2">P2-7</text>
<text x="91.4" y="80">P2-8</text>
<text x="91.4" y="81.9">P2-9</text>
<text x="105.5" y="79.4">WAR</text>
<text x="105.5" y="83.1">WPC</text>
<text x="105.5" y="81.2">WDR</text>
<text x="146.5" y="83.1">AB5</text>
<text x="146.5" y="81.2">AB4</text>
<text x="146.5" y="79.4">AB3</text>
<text x="185.6" y="81.2">[R1]</text>
<text x="185.6" y="83.1">[R6]</text>
<text x="186" y="79.4">WS</text>
<text x="224.3" y="83.1">DB5</text>
<text x="224.3" y="81.2">DB4</text>
<text x="224.3" y="79.4">DB3</text>
<text x="62.6" y="85.6">P1-11</text>
<text x="62.6" y="87.4">P1-12</text>
<text x="62.6" y="89.3">P1-13</text>
<text x="77.7" y="86.8">RUNIT1</text>
<text x="77.7" y="88.6">RUNIT2</text>
<text x="77.7" y="84.9">RUNIT0</text>
<text x="90.4" y="85.6">P2-11</text>
<text x="90.4" y="87.4">P2-12</text>
<text x="90.4" y="89.3">P2-13</text>
<text x="105.5" y="84.9">FNEG</text>
<text x="105.5" y="86.8">FZERO</text>
<text x="105.5" y="88.6">PC10</text>
<text x="145.7" y="88.6">IRQ3</text>
<text x="146.5" y="86.8">AB7</text>
<text x="146.5" y="84.9">AB6</text>
<text x="183.1" y="88.6">AEXT0</text>
<text x="185.2" y="86.8">[W1]</text>
<text x="185.6" y="84.9">[R7]</text>
<text x="223.6" y="88.6">MEM</text>
<text x="224.3" y="86.8">DB7</text>
<text x="224.3" y="84.9">DB6</text>
<text x="62.6" y="91.1">P1-14</text>
<text x="62.6" y="93">P1-15</text>
<text x="62.6" y="94.9">P1-16</text>
<text x="77.7" y="90.5">RUNIT3</text>
<text x="77.7" y="92.4">SKIP</text>
<text x="77.7" y="94.2">STI</text>
<text x="90.4" y="91.1">P2-14</text>
<text x="90.4" y="93">P2-15</text>
<text x="90.4" y="94.9">P2-16</text>
<text x="105.5" y="90.5">PC11</text>
<text x="105.5" y="92.4">PC12</text>
<text x="105.5" y="94.2">PC13</text>
<text x="127.7" y="94.2">IBUS[0..15]</text>
<text x="145.7" y="90.5">IRQ4</text>
<text x="145.7" y="92.4">IRQ5</text>
<text x="145.7" y="94.2">IRQ6</text>
<text x="183.1" y="94.2">AEXT3</text>
<text x="183.1" y="92.4">AEXT2</text>
<text x="183.1" y="90.5">AEXT1</text>
<text x="225.9" y="90.5">IO</text>
<text x="226.1" y="94.2">W</text>
<text x="226.5" y="92.4">R</text>
<text x="62.6" y="96.7">P1-17</text>
<text x="62.6" y="98.6">P1-18</text>
<text x="62.6" y="100.4">P1-19</text>
<text x="77.7" y="97.9">OPIF0</text>
<text x="77.7" y="99.8">OPIF1</text>
<text x="77.7" y="101.6">OPIF2</text>
<text x="77.7" y="96.1">CLI</text>
<text x="90.4" y="96.7">P2-17</text>
<text x="90.4" y="98.6">P2-18</text>
<text x="90.4" y="100.4">P2-19</text>
<text x="105.5" y="96.1">PC14</text>
<text x="105.5" y="97.9">PC15</text>
<text x="105.5" y="99.8">WIR</text>
<text x="105.5" y="101.6">AINDEX</text>
<text x="145.5" y="99.8">HALT</text>
<text x="145.7" y="97.9">IRQ7</text>
<text x="145.9" y="96.1">*TPA</text>
<text x="146.5" y="101.6">AB8</text>
<text x="164.8" y="96.1">(2)</text>
<text x="183.1" y="101.6">AEXT7</text>
<text x="183.1" y="99.8">AEXT6</text>
<text x="183.1" y="97.9">AEXT5</text>
<text x="183.1" y="96.1">AEXT4</text>
<text x="223.5" y="96.1">*TPC</text>
<text x="223.6" y="97.9">IRQ0</text>
<text x="223.6" y="101.6">IRQ2</text>
<text x="223.6" y="99.8">IRQ1</text>
<text x="242.7" y="96.1">(2)</text>
<text x="62.6" y="102.3">P1-20</text>
<text x="62.6" y="104.1">P1-21</text>
<text x="62.6" y="106">P1-22</text>
<text x="62.6" y="107.8">P1-23</text>
<text x="77.7" y="107.2">AC0</text>
<text x="77.7" y="103.5">OPIF3</text>
<text x="77.7" y="105.3">IR11</text>
<text x="90.4" y="102.3">P2-20</text>
<text x="90.4" y="104.1">P2-21</text>
<text x="90.4" y="106">P2-22</text>
<text x="90.4" y="107.8">P2-23</text>
<text x="105.5" y="103.5">IBUS0</text>
<text x="105.5" y="105.3">IBUS1</text>
<text x="105.5" y="107.2">IBUS2</text>
<text x="145.5" y="107.2">AB11</text>
<text x="145.5" y="105.3">AB10</text>
<text x="146.5" y="103.5">AB9</text>
<text x="180.3" y="105.3">RSTHOLD</text>
<text x="203.7" y="103.5">(3)</text>
<text x="203.7" y="107.2">(3)</text>
<text x="223.3" y="107.2">DB10</text>
<text x="224.3" y="105.3">DB9</text>
<text x="224.3" y="103.5">DB8</text>
<text x="62.6" y="109.7">P1-24</text>
<text x="62.6" y="111.5">P1-25</text>
<text x="62.6" y="113.4">P1-26</text>
<text x="77.7" y="109">AC1</text>
<text x="77.7" y="110.9">AC2</text>
<text x="77.7" y="112.7">AC3</text>
<text x="90.4" y="109.7">P2-24</text>
<text x="90.4" y="111.5">P2-25</text>
<text x="90.4" y="113.4">P2-26</text>
<text x="105.5" y="109">IBUS3</text>
<text x="105.5" y="110.9">IBUS4</text>
<text x="105.5" y="112.7">IBUS5</text>
<text x="145.5" y="112.7">AB14</text>
<text x="145.5" y="110.9">AB13</text>
<text x="145.5" y="109">AB12</text>
<text x="179.8" y="112.7">IODEV3XX</text>
<text x="179.8" y="110.9">IODEV2XX</text>
<text x="179.8" y="109">IODEV1XX</text>
<text x="223.3" y="112.7">DB13</text>
<text x="223.3" y="110.9">DB12</text>
<text x="223.3" y="109">DB11</text>
<text x="62.6" y="115.2">P1-27</text>
<text x="62.6" y="117.1">P1-28</text>
<text x="62.6" y="119">P1-29</text>
<text x="77.7" y="114.6">AC4</text>
<text x="77.7" y="116.5">AC5</text>
<text x="77.7" y="118.3">AC6</text>
<text x="90.4" y="115.2">P2-27</text>
<text x="90.4" y="117.1">P2-28</text>
<text x="90.4" y="119">P2-29</text>
<text x="105.5" y="116.5">IBUS7</text>
<text x="105.5" y="118.3">IBUS8</text>
<text x="105.5" y="114.6">IBUS6</text>
<text x="142.8" y="116.5">SYSDEV</text>
<text x="145.4" y="118.3">CLK1</text>
<text x="145.5" y="114.6">AB15</text>
<text x="184.4" y="118.3">CLK2</text>
<text x="184.4" y="116.5">CLK4</text>
<text x="185.8" y="114.6">T34</text>
<text x="223.3" y="116.5">DB15</text>
<text x="223.3" y="114.6">DB14</text>
<text x="224.6" y="118.3">IRQ</text>
<text x="242.7" y="118.3">(5)</text>
<text x="62.6" y="120.8">P1-30</text>
<text x="62.6" y="122.7">P1-31</text>
<text x="62.6" y="124.5">P1-32</text>
<text x="77.7" y="120.2">AC7</text>
<text x="77.7" y="122">AC8</text>
<text x="77.7" y="123.9">AC9</text>
<text x="77.7" y="125.7">AC10</text>
<text x="90.4" y="120.8">P2-30</text>
<text x="90.4" y="122.7">P2-31</text>
<text x="90.4" y="124.5">P2-32</text>
<text x="105.5" y="120.2">IBUS9</text>
<text x="105.5" y="122">IBUS10</text>
<text x="105.5" y="123.9">IBUS11</text>
<text x="105.5" y="125.7">IBUS12</text>
<text x="123.1" y="120.2" transform="rotate(-90 123.1 120.2)">IBUS[0..15]</text>
<text x="145.5" y="120.2">IRQS</text>
<text x="145.9" y="122">GND</text>
<text x="146.2" y="123.9">VCC</text>
<text x="184.4" y="120.2">CLK3</text>
<text x="184.9" y="122">GND</text>
<text x="185.2" y="123.9">VCC</text>
<text x="221.8" y="120.2">RESET</text>
<text x="223.8" y="122">GND</text>
<text x="224.1" y="123.9">VCC</text>
<text x="62.6" y="126.4">P1-33</text>
<text x="62.6" y="128.2">P1-34</text>
<text x="62.6" y="130.1">P1-35</text>
<text x="62.6" y="131.9">P1-36</text>
<text x="77.7" y="129.4">AC12</text>
<text x="77.7" y="127.6">AC11</text>
<text x="77.7" y="131.3">AC13</text>
<text x="90.4" y="126.4">P2-33</text>
<text x="90.4" y="128.2">P2-34</text>
<text x="90.4" y="130.1">P2-35</text>
<text x="90.4" y="131.9">P2-36</text>
<text x="105.5" y="127.6">IBUS13</text>
<text x="105.5" y="129.4">IBUS14</text>
<text x="105.5" y="131.3">IBUS15</text>
<text x="150" y="129.4">PCB @ (0, 1.95)</text>
<text x="172.2" y="129.4">(4)</text>
<text x="62.6" y="133.8">P1-37</text>
<text x="62.6" y="135.6">P1-38</text>
<text x="62.6" y="137.5">P1-39</text>
<text x="77.7" y="133.1">AC14</text>
<text x="77.7" y="135">AC15</text>
<text x="77.7" y="136.8">ACCPL</text>
<text x="90.4" y="133.8">P2-37</text>
<text x="90.4" y="135.6">P2-38</text>
<text x="90.4" y="137.5">P2-39</text>
<text x="105.5" y="133.1">IR12</text>
<text x="105.5" y="135">IR13</text>
<text x="105.5" y="136.8">IR14</text>
<text x="62.6" y="139.3">P1-40</text>
<text x="77.7" y="138.7">DEC</text>
<text x="90.4" y="139.3">P2-40</text>
<text x="105.5" y="138.7">IR15</text>
<text x="150" y="138.7">Notes</text>
<text x="105.5" y="149.8" transform="rotate(-90 105.5 149.8)">VCC</text>
<text x="112.9" y="149.8" transform="rotate(-90 112.9 149.8)">VCC</text>
<text x="120.3" y="149.8" transform="rotate(-90 120.3 149.8)">VCC</text>
<text x="127.7" y="149.8" transform="rotate(-90 127.7 149.8)">VCC</text>
<text x="150" y="149.8">(2) Pins *TPA and *TPC are not bussed. They are locally connected to each card's corresponding</text>
<text x="150" y="144.3">(1) This pin is connected to a bus bar for power distribution, but the CFT does not (yet) require it.</text>
<text x="153.7" y="146.1">It's likely to be connected to another voltage level like +3.3V for easier interfacing. Reserved for now.</text>
<text x="108.4" y="153.3">C36</text>
<text x="115.9" y="153.3">C37</text>
<text x="123" y="153.2">C38</text>
<text x="130.4" y="153.2">C39</text>
<text x="150" y="155.4">(3) Reserved for future expansion</text>
<text x="153.7" y="151.7">test pins (A17 &amp; C17) to serve as test points.</text>
<text x="108.4" y="157">1uF</text>
<text x="115.9" y="157">1uF</text>
<text x="123" y="156.9">47uF</text>
<text x="130.4" y="156.9">47uF</text>
<text x="150" y="159.1">(4) Cheaper, 64-pin A+C row DIN41662 Type C plugs may be used for most expansion cards.</text>
<text x="105.1" y="162.8">GND</text>
<text x="112.6" y="162.8">GND</text>
<text x="120" y="162.8">GND</text>
<text x="127.4" y="162.8">GND</text>
<text x="150" y="162.8">(5) IRQ is provided for systems which lack an interrupt controller (IRQ0-7)</text>
<text x="18" y="179.4">HOLE</text>
<text x="18" y="177.2">U1</text>
<text x="37.9" y="179.4">HOLE</text>
<text x="40.5" y="177.2">U3</text>
<text x="16.5" y="181.3">@(0.15, 3.675)</text>
<text x="31.1" y="181.3">@(5.775, 3.675)</text>
<text x="18" y="190.6">HOLE</text>
<text x="18" y="188.3">U2</text>
<text x="37.9" y="190.6">HOLE</text>
<text x="40.5" y="188.3">U4</text>
<text x="16.5" y="192.5">@(0.15, 0.25)</text>
<text x="32.1" y="192.5">@(5.775, 0.25)</text>
</g>
<g font-size="1.6">
<text x="157.5" y="66.1">A1</text>
<text x="157.5" y="68">A2</text>
<text x="157.5" y="69.9">A3</text>
<text x="157.5" y="71.7">A4</text>
<text x="196.4" y="66.1">B1</text>
<text x="196.4" y="68">B2</text>
<text x="196.4" y="69.9">B3</text>
<text x="196.4" y="71.7">B4</text>
<text x="235.3" y="66.1">C1</text>
<text x="235.3" y="68">C2</text>
<text x="235.3" y="69.9">C3</text>
<text x="235.3" y="71.7">C4</text>
<text x="157.5" y="73.6">A5</text>
<text x="157.5" y="75.4">A6</text>
<text x="157.5" y="77.3">A7</text>
<text x="196.4" y="73.6">B5</text>
<text x="196.4" y="75.4">B6</text>
<text x="196.4" y="77.3">B7</text>
<text x="235.3" y="73.6">C5</text>
<text x="235.3" y="75.4">C6</text>
<text x="235.3" y="77.3">C7</text>
<text x="156.6" y="82.8">A10</text>
<text x="157.5" y="79.1">A8</text>
<text x="157.5" y="81">A9</text>
<text x="195.5" y="82.8">B10</text>
<text x="196.4" y="79.1">B8</text>
<text x="196.4" y="81">B9</text>
<text x="234.4" y="82.8">C10</text>
<text x="235.3" y="79.1">C8</text>
<text x="235.3" y="81">C9</text>
<text x="156.6" y="84.7">A11</text>
<text x="156.6" y="86.5">A12</text>
<text x="156.6" y="88.4">A13</text>
<text x="195.5" y="84.7">B11</text>
<text x="195.5" y="86.5">B12</text>
<text x="195.5" y="88.4">B13</text>
<text x="234.4" y="84.7">C11</text>
<text x="234.4" y="86.5">C12</text>
<text x="234.4" y="88.4">C13</text>
<text x="156.6" y="90.2">A14</text>
<text x="156.6" y="92.1">A15</text>
<text x="156.6" y="93.9">A16</text>
<text x="156.6" y="95.8">A17</text>
<text x="195.5" y="90.2">B14</text>
<text x="195.5" y="92.1">B15</text>
<text x="195.5" y="93.9">B16</text>
<text x="195.5" y="95.8">B17</text>
<text x="234.4" y="90.2">C14</text>
<text x="234.4" y="92.1">C15</text>
<text x="234.4" y="93.9">C16</text>
<text x="234.4" y="95.8">C17</text>
<text x="156.6" y="97.7">A18</text>
<text x="156.6" y="99.5">A19</text>
<text x="156.6" y="101.4">A20</text>
<text x="195.5" y="97.7">B18</text>
<text x="195.5" y="99.5">B19</text>
<text x="195.5" y="101.4">B20</text>
<text x="234.4" y="97.7">C18</text>
<text x="234.4" y="99.5">C19</text>
<text x="234.4" y="101.4">C20</text>
<text x="156.6" y="103.2">A21</text>
<text x="156.6" y="105.1">A22</text>
<text x="156.6" y="106.9">A23</text>
<text x="195.5" y="103.2">B21</text>
<text x="195.5" y="105.1">B22</text>
<text x="195.5" y="106.9">B23</text>
<text x="234.4" y="103.2">C21</text>
<text x="234.4" y="105.1">C22</text>
<text x="234.4" y="106.9">C23</text>
<text x="156.6" y="108.8">A24</text>
<text x="156.6" y="110.6">A25</text>
<text x="156.6" y="112.5">A26</text>
<text x="195.5" y="108.8">B24</text>
<text x="195.5" y="110.6">B25</text>
<text x="195.5" y="112.5">B26</text>
<text x="234.4" y="108.8">C24</text>
<text x="234.4" y="110.6">C25</text>
<text x="234.4" y="112.5">C26</text>
<text x="156.6" y="114.3">A27</text>
<text x="156.6" y="116.2">A28</text>
<text x="156.6" y="118">A29</text>
<text x="156.6" y="119.9">A30</text>
<text x="195.5" y="114.3">B27</text>
<text x="195.5" y="116.2">B28</text>
<text x="195.5" y="118">B29</text>
<text x="195.5" y="119.9">B30</text>
<text x="234.4" y="114.3">C27</text>
<text x="234.4" y="116.2">C28</text>
<text x="234.4" y="118">C29</text>
<text x="234.4" y="119.9">C30</text>
<text x="156.6" y="121.8">A31</text>
<text x="156.6" y="123.6">A32</text>
<text x="195.5" y="121.8">B31</text>
<text x="195.5" y="123.6">B32</text>
<text x="234.4" y="121.8">C31</text>
<text x="234.4" y="123.6">C32</text>
</g>
<g font-size="1.3">
<text x="121.7" y="153.2" transform="rotate(-90 121.7 153.2)">+</text>
<text x="129.2" y="153.2" transform="rotate(-90 129.2 153.2)">+</text>
<text x="144.4" y="188.8">[PCB Logo]</text>
<text x="144.4" y="192.5">[QR Code http://www.bedroomlan.org/cft (shortened)]</text>
</g>
</g></defs>
<g fill="none" stroke="#000" stroke-width=".18">
<path d="M10 12.6h277.2v184.5h-277.2zM44.6 9.9v2.7M79.3 9.9v2.7M113.9 9.9v2.7M148.6 9.9v2.7M183.2 9.9v2.7M217.9 9.9v2.7M252.5 9.9v2.7M7.2 49.5h2.8M171.1 59h-.7v.7M171.8 59h.8M173.3 59h.7"/>
<path d="M174.8 59h.7M176.2 59h.8M177.7 59h.8M179.2 59h.7M180.7 59h.7M182.1 59h.8M183.6 59h.7M185.1 59h.7M186.5 59h.8M188 59h.7M189.5 59h.7M190.9 59h.8"/>
<path d="M192.4 59h.7M193.9 59h.7M195.3 59h.8M196.8 59h.7M198.3 59h.7M199.7 59h.8M201.2 59h.8M202.7 59h.7M204.2 59h.7M205.6 59h.8M207.1 59h.7M208.6 59h.7v.7"/>
<path d="M287.2 49.5h2.7M70.3 66.4h5.5M70.3 68.3h5.5M70.3 70.1h5.5M70.3 72h5.5M70.3 73.8h5.5M70.3 75.7h5.5M70.3 77.5h5.5M70.3 79.4h5.5M77.7 77.9h4.2M77.7 66.8h3.5M77.7 68.7h4.8"/>
<path d="M77.7 65h3.3M77.7 70.5h5.1M98.1 66.4h5.5M98.1 68.3h5.5M98.1 70.1h5.5M98.1 72h5.5M98.1 73.8h5.5M98.1 75.7h5.5M98.1 77.5h5.5M98.1 79.4h5.5M105.5 74.2h3.8M105.5 76.1h4.1"/>
<path d="M105.5 77.9h4.1M105.5 66.8h6.1M105.5 68.7h5.6M105.5 65h5.8M105.5 72.4h3.9M105.5 70.5h3.7M105.5 79.8h4.3M150 66.4h11.1M150 68.3h11.1M150 70.1h11.1M150 72h11.1M150 73.8h11.1"/>
<path d="M150 75.7h11.1M150 77.5h11.1M150 79.4h11.1M170.4 60.5v.7M170.4 61.9v.7M170.4 63.4v.7M170.4 64.8v.8M170.4 66.3v.7M170.4 67.8v.7M170.4 69.2v.7M170.4 70.7v.7M170.4 72.1v.8"/>
<path d="M170.4 73.6v.7M170.4 75.1v.7M170.4 76.5v.7M170.4 78v.7M170.4 79.4v.8M181.3 74.2h7.6M181.5 76.1h7.4M185.6 79.8h3.3M186 77.9h2.9M188.9 66.4h11.1M188.9 68.3h11.1M188.9 70.1h11.1"/>
<path d="M188.9 72h11.1M188.9 75.7h11.1M188.9 77.5h11.1M188.9 79.4h11.1M194.5 73.8h5.5M209.3 60.5v.7M209.3 61.9v.7M209.3 63.4v.7M209.3 64.8v.8M209.3 66.3v.7M209.3 67.8v.7M209.3 69.2v.7"/>
<path d="M209.3 70.7v.7M209.3 72.1v.8M209.3 73.6v.7M209.3 75.1v.7M209.3 76.5v.7M209.3 78v.7M209.3 79.4v.8M227.8 66.4h11.2M227.8 68.3h11.2M227.8 70.1h11.2M227.8 72h11.2M227.8 73.8h11.2"/>
<path d="M227.8 75.7h11.2M227.8 77.5h11.2M227.8 79.4h11.2M7.2 86.4h2.8M70.3 81.2h5.5M70.3 83.1h5.5M70.3 84.9h5.5M70.3 86.8h5.5M70.3 88.6h5.5M70.3 90.5h5.5M70.3 92.4h5.5M70.3 94.2h5.5"/>
<path d="M70.3 96.1h5.5M70.3 97.9h5.5M70.3 99.8h5.5M77.7 90.9h4.1M77.7 92.8h2.7M77.7 81.6h3.8M77.7 94.6h2.8M98.1 81.2h5.5M98.1 83.1h5.5M98.1 84.9h5.5M98.1 86.8h5.5M98.1 88.6h5.5"/>
<path d="M98.1 90.5h5.5M98.1 92.4h5.5M98.1 94.2h5.5M98.1 96.1h5.5M98.1 97.9h5.5M98.1 99.8h5.5M105.5 98.3h3.5M105.5 81.6h4.2M145.5 98.3h4.5M145.7 87.2h4.3M145.7 89.1h4.3M145.7 90.9h4.3"/>
<path d="M145.7 92.8h4.3M145.7 96.5h4.3M150 81.2h11.1M150 83.1h11.1M150 84.9h11.1M150 86.8h11.1M150 88.6h11.1M150 90.5h11.1M150 92.4h11.1M150 94.2h11.1M150 96.1h11.1M150 97.9h11.1"/>
<path d="M150 99.8h11.1M170.4 80.9v.7M170.4 82.4v.7M170.4 83.8v.7M170.4 85.3v.7M170.4 86.7v.8M170.4 88.2v.7M170.4 89.7v.7M170.4 91.1v.7M170.4 92.6v.7M170.4 94v.8M170.4 95.5v.7"/>
<path d="M170.4 97v.7M170.4 98.4v.7M170.4 99.9v.7M185.2 85.4h3.7M185.6 81.6h3.3M185.6 83.5h3.3M188.9 81.2h11.1M188.9 83.1h11.1M188.9 84.9h11.1M188.9 86.8h11.1M188.9 88.6h11.1M188.9 90.5h11.1"/>
<path d="M188.9 92.4h11.1M188.9 94.2h11.1M188.9 96.1h11.1M188.9 97.9h11.1M188.9 99.8h11.1M209.3 80.9v.7M209.3 82.4v.7M209.3 83.8v.7M209.3 85.3v.7M209.3 86.7v.8M209.3 88.2v.7M209.3 89.7v.7"/>
<path d="M209.3 91.1v.7M209.3 92.6v.7M209.3 94v.8M209.3 95.5v.7M209.3 97v.7M209.3 98.4v.7M209.3 99.9v.7M223.6 87.2h4.2M223.6 98.3h4.2M223.6 96.5h4.2M225.9 89.1h1.9M226.1 92.8h1.7"/>
<path d="M226.5 90.9h1.3M227.8 81.2h11.2M227.8 83.1h11.2M227.8 84.9h11.2M227.8 86.8h11.2M227.8 88.6h11.2M227.8 90.5h11.2M227.8 92.4h11.2M227.8 94.2h11.2M227.8 96.1h11.2M227.8 97.9h11.2M227.8 99.8h11.2"/>
<path d="M287.2 86.4h2.7M70.3 101.6h5.5M70.3 103.5h5.5M70.3 105.3h5.5M70.3 107.2h5.5M70.3 109h5.5M70.3 110.9h5.5M70.3 112.8h5.5M70.3 114.6h5.5M70.3 116.5h5.5M70.3 118.3h5.5M98.1 101.6h5.5"/>
<path d="M105.5 100.2h6.7M120.3 101.6l-1.9 1.9h-20.3M120.3 103.5l-1.9 1.8h-20.3M120.3 105.3l-1.9 1.9h-20.3M120.3 107.2l-1.9 1.8h-20.3M120.3 109l-1.9 1.9h-20.3M120.3 110.9l-1.9 1.9h-20.3M120.3 112.8l-1.9 1.8h-20.3M120.3 114.6l-1.9 1.9h-20.3M120.3 116.5l-1.9 1.8h-20.3M120.3 118.3l-1.9 1.9h-20.3M142.8 115h7.2"/>
<path d="M145.5 118.7h4.5M150 101.6h11.1M150 103.5h11.1M150 105.3h11.1M150 107.2h11.1M150 109h11.1M150 110.9h11.1M150 112.8h11.1M150 114.6h11.1M150 116.5h11.1M150 118.3h11.1M170.4 101.3v.8"/>
<path d="M170.4 102.8v.7M170.4 104.3v.7M170.4 105.7v.7M170.4 107.2v.7M170.4 108.6v.8M170.4 110.1v.7M170.4 111.6v.7M170.4 113v.7M170.4 114.5v.7M170.4 116v.7M170.4 117.4v.7M170.4 118.9v.7"/>
<path d="M179.8 111.3h9.1M179.8 109.5h9.1M179.8 107.6h9.1M180.3 103.9h8.6M185.8 113.2h3.1M188.9 101.6h11.1M188.9 105.3h11.1M188.9 109h11.1M188.9 110.9h11.1M188.9 112.8h11.1M188.9 114.6h11.1M188.9 116.5h11.1"/>
<path d="M188.9 118.3h11.1M194.5 103.5h5.5M194.5 107.2h5.5M209.3 101.3v.8M209.3 102.8v.7M209.3 104.3v.7M209.3 105.7v.7M209.3 107.2v.7M209.3 108.6v.8M209.3 110.1v.7M209.3 111.6v.7M209.3 113v.7"/>
<path d="M209.3 114.5v.7M209.3 116v.7M209.3 117.4v.7M209.3 118.9v.7M221.8 118.7h6M223.6 100.2h4.2M224.6 116.9h3.2M227.8 101.6h11.2M227.8 103.5h11.2M227.8 105.3h11.2M227.8 107.2h11.2M227.8 109h11.2"/>
<path d="M227.8 110.9h11.2M227.8 112.8h11.2M227.8 114.6h11.2M227.8 116.5h11.2M227.8 118.3h11.2M7.2 123.3h2.8M70.3 120.2h5.5M70.3 122h5.5M70.3 123.9h5.5M70.3 125.7h5.5M70.3 127.6h5.5M70.3 129.4h5.5"/>
<path d="M70.3 131.3h5.5M70.3 133.1h5.5M70.3 135h5.5M70.3 136.8h5.5M70.3 138.7h5.5M77.7 135.4h6M77.7 137.3h3.8M98.1 133.1h5.5M98.1 135h5.5M98.1 136.8h5.5M98.1 138.7h5.5M120.3 120.2l-1.9 1.8h-20.3"/>
<path d="M120.3 122l-1.9 1.9h-20.3M120.3 123.9l-1.9 1.8h-20.3M120.3 125.7l-1.9 1.9h-20.3M120.3 127.6l-1.9 1.8h-20.3M120.3 129.4l-1.9 1.9h-20.3M150 120.2h11.1M150 122h11.1M150 123.9h11.1M170.4 130.6v.7h.7M170.4 120.3v.8M170.4 121.8v.7M170.4 123.3v.7"/>
<path d="M170.4 124.7v.7M170.4 126.2v.7M170.4 127.6v.8M170.4 129.1v.7M171.8 131.3h.8M173.3 131.3h.7M174.8 131.3h.7M176.2 131.3h.8M177.7 131.3h.8M179.2 131.3h.7M180.7 131.3h.7M182.1 131.3h.8"/>
<path d="M183.6 131.3h.7M185.1 131.3h.7M186.5 131.3h.8M188 131.3h.7M188.9 120.2h11.1M188.9 122h11.1M188.9 123.9h11.1M189.5 131.3h.7M190.9 131.3h.8M192.4 131.3h.7M193.9 131.3h.7M195.3 131.3h.8"/>
<path d="M196.8 131.3h.7M198.3 131.3h.7M199.7 131.3h.8M201.2 131.3h.8M202.7 131.3h.7M204.2 131.3h.7M205.6 131.3h.8M207.1 131.3h.7M209.3 130.6v.7h-.7M209.3 120.3v.8M209.3 121.8v.7M209.3 123.3v.7"/>
<path d="M209.3 124.7v.7M209.3 126.2v.7M209.3 127.6v.8M209.3 129.1v.7M227.8 120.2h11.2M227.8 122h11.2M227.8 123.9h11.2M287.2 123.3h2.7M107.3 148v5.9M107.3 155v6M114.7 148v5.9M114.7 155v6"/>
<path d="M122.2 148v5.5M122.2 155.4v5.6M129.6 148v5.5M129.6 155.4v5.6M7.2 160.2h2.8M12.8 173.9h35.2v20.4h-35.2zM16.1 177.6h.7M16.5 177.3v.7M43.9 177.6h.8M44.3 177.3v.7M152.7 161.4h3.3M202.8 161.4h5.9"/>
<path d="M287.2 160.2h2.7M16.1 188.8h.7M16.5 188.4v.7M43.9 188.8h.8M44.3 188.4v.7M44.6 197.1v2.8M79.3 197.1v2.8M113.9 197.1v2.8M148.6 197.1v2.8M180.5 192.5h.3M180.5 192.4h.3M180.5 192.3h.3"/>
<path d="M180.5 192.2h.3M180.5 192.1h.3M180.5 192h.3M180.5 191.9h.3M180.6 192.6h.3M180.6 192.5h.2M180.6 191.9h.2M180.6 191.8h.2M180.6 192.6l.4 .1M180.6 192.7h1M180.6 191.7h.9M180.6 192.7h.9"/>
<path d="M180.6 191.6h.9M180.7 192.8h.8M180.7 191.6h.8M180.7 192.9h.7M180.7 191.5h.7M180.8 191.5h.6M180.8 192.9h.5M180.9 193h.3M180.9 191.8h-.3M180.9 191.4h.3M181 191.7h-.4M181.2 191.7h.4"/>
<path d="M181.2 192.7h.4M181.2 192.6h.4M181.2 191.8h.4M181.3 192.6h.3M181.3 191.8l.3 .1M181.3 192.5h.3M181.3 192.4h.3M181.3 192.3h.3M181.3 192.2h.3M181.3 192.1h.3M181.3 192h.3M181.3 191.9h.3"/>
<path d="M181.6 192.5h-.3M181.9 193.3h.3M181.9 193.2h.3M181.9 193.1h.3M181.9 193h.3M181.9 192.7h1M181.9 192.7h1.1M181.9 192.6l.5 .1M181.9 192.6h.4M181.9 192.5h.3M181.9 192.4h.3M181.9 192.3h.3"/>
<path d="M181.9 192.2h.3M181.9 192.1h.3M181.9 192h.3M181.9 191.9h.3M181.9 193.5h.2M182 191.7h1M182 191.7h.9M182 191.6h.9M182.1 191.6h.8M182.1 191.5h.7M182.2 193.4h-.3M182.2 191.5h.6"/>
<path d="M182.3 191.8l-.4 .1M182.3 193h.3M182.3 191.8h-.4M182.3 191.4h.3M182.4 191.7h-.4M182.6 191.7h.4M182.6 192.7h.4M182.6 191.8h.4M182.6 192.6h.4M182.7 192.6h.3M182.7 192.5h.3M182.7 191.8l.3 .1"/>
<path d="M182.7 191.9h.3M182.7 192.9h-.8M182.7 192.4h.3M182.7 192.3h.3M182.7 192.2h.3M182.7 192.1h.3M182.7 192h.3M182.8 192.9h-.9M182.8 192.8h-.9M182.9 192.8h-1M183.2 197.1v2.8M183.3 192.6l.5 .1"/>
<path d="M183.3 192.6h.4M183.3 192.5h.3M183.3 192.1h1.1M183.3 192l.3 .1M183.3 192h.3M183.3 191.8h.4M183.4 192.7h.9M183.4 191.7h.9M183.4 191.6h.9M183.5 192.8h.8M183.5 191.6h.8M183.5 192.8h.7"/>
<path d="M183.5 191.5h.7M183.5 192.9h.7M183.6 191.5h.5M183.6 192.9h.5M183.6 191.9h-.3M183.7 192.4h-.4M183.7 192.1h.7M183.7 191.8h-.4M183.7 193h.3M183.7 191.4h.3M183.8 191.7h-.4M183.8 192.4h-.5"/>
<path d="M183.9 192h.5M183.9 192.3h-.6M184 192h.4M184 191.7h.4M184 192.3h-.7M184 191.8h.4M184.1 192.6h.3M184.1 191.9h.3M184.1 191.8h.3M184.1 192.5h.3M184.1 192.4h.3M184.1 192.2l-.8 .1"/>
<path d="M184.2 192.3h.2M184.2 192.2h-.9M184.3 192.2h-1M184.3 192.3h.1M184.4 192.6l-.4 .1M184.4 192.6h-.4M184.7 192.9h.2M184.7 192.8h.3M184.7 192.7h.3M184.7 192.6h.3M184.7 192.5h.3M184.7 192.4h.3"/>
<path d="M184.7 192.3h.3M184.7 192.2h.3M184.7 192.1h.3M184.7 192h.3M184.7 191.9h.3M184.8 193h.1M184.8 191.7h.9M184.8 191.6h.9M184.9 191.6h.8M184.9 191.5h.7M185 191.5h.5M185 192.9h-.3"/>
<path d="M185 191.9h-.3M185.1 191.8l-.4 .1M185.1 191.8h-.4M185.1 191.4h.3M185.2 191.7h-.4M185.4 191.7h.4M185.4 191.8h.4M185.5 191.8l.3 .1M185.5 192.9h.2M185.5 192.8h.3M185.5 192.7h.3M185.5 192.6h.3"/>
<path d="M185.5 192.5h.3M185.5 192.4h.3M185.5 192.3h.3M185.5 192.2h.3M185.5 192.1h.3M185.5 192h.3M185.5 191.9h.3M185.5 193h.1M185.7 191.7h-.9M185.8 192.9h-.3M187 192.9h.2M187 192.8h.2"/>
<path d="M187 192.7h.2M187 192.6h.2M187 192.5h.2M187 192.4h.2M187 192.3h.2M187 192.2h.2M187 192.1h.2M187 192h.2M187 191.9h.2M187 191.7h.9M187 191.6l.9 .1M187 191.6h.8"/>
<path d="M187 191.6h.7M187 191.5h.2M187 191.4h.2M187 191.3h.2M187 191.2h.2M187 191.1h.2M187.1 191h.1M187.1 193h-.1M187.2 192.9h-.2M187.3 191.8l-.3 .1M187.3 191.5h.4M187.4 191.8h-.4"/>
<path d="M187.5 191.7h-.5M187.5 191.7h.4M187.6 191.8h.4M187.7 191.8l.3 .1M187.7 191.9h.3M187.8 191.9h.2M187.8 193h.1M187.8 192.9h.2M187.8 192.8h.2M187.8 192.7h.2M187.8 192.6h.2M187.8 192.5h.2"/>
<path d="M187.8 192.4h.2M187.8 192.3h.2M187.8 192.2h.2M187.8 192.1h.2M187.8 192h.2M188 192.9h-.2M188.3 192.6h.3M188.3 192.6h.2M188.3 192h.2M188.3 192.7l.4 .1M188.3 192.7h.3M188.3 192.5h.3"/>
<path d="M188.3 192.1h.1M188.3 191.9h.3M188.4 192.8h.6M188.4 192.9h.6M188.4 191.7h.8M188.5 191.7h.7M188.5 192.9h.5M188.5 192l-.2 .1M188.5 191.6h.6M188.5 192h-.2M188.6 192.6h-.3M188.6 192.3h.7"/>
<path d="M188.6 191.9h-.3M188.6 193h.4M188.6 192.5h-.3M188.6 191.6h.5M188.6 191.8l-.2 .1M188.7 192.2h.6M188.7 191.5h.3M188.7 191.8h-.3M188.7 192.4h-.4M188.7 193h.1M188.8 192.8h.1M188.9 192.4h-.5"/>
<path d="M188.9 192.1h.4M189 192.3h-.6M189 191.8h.3M189.1 192h.2M189.1 191.9h.2M189.1 192.8h.2M189.1 192.7h.2M189.1 192.6h.2M189.1 192.5h.2M189.1 192.4h.2M189.1 192.3h.2M189.2 193h-.1"/>
<path d="M189.3 191.7h-.9M189.3 192.9h-.2M189.3 192.3h-.8M189.7 192.9h.2M189.7 192.8h.2M189.7 192.7h.2M189.7 192.6h.2M189.7 192.5h.2M189.7 192.4h.2M189.7 192.3h.2M189.7 192.2h.2M189.7 192.1h.2"/>
<path d="M189.7 192h.2M189.7 191.9h.2M189.7 191.7h.8M189.8 193h-.1M189.8 191.7h.7M189.8 191.6h.7M189.8 192.9h-.1M189.9 191.6h.5M189.9 191.8l-.2 .1M190 191.5h.3M190 191.8h-.3M190.3 191.8h.3"/>
<path d="M190.4 191.8l.2 .1M190.4 191.9h.2M190.4 192h.2M190.6 191.7h-.9M190.6 192l-.1 .1M190.6 192h-.2M191 192.6h.2M191 192.5h.2M191 192.4h.2M191 192.3h.2M191 192.2h.2M191 192.1h.2"/>
<path d="M191 192h.2M191 191.9h.2M191 192.6l.2 .1M191 192.7h.3M191 192.7l.4 .1M191.1 192.8h.8M191.1 191.7h.9M191.1 192.9h.7M191.1 191.6h.9M191.2 191.6h.8M191.2 192.9h.6M191.2 191.9h-.2"/>
<path d="M191.3 193h.4M191.3 191.8l-.3 .1M191.3 191.5h.3M191.3 191.8h-.3M191.4 193h.1M191.4 191.7h-.3M191.5 193h.1M191.5 191.7h.5M191.6 191.8h.4M191.7 191.8h.3M191.7 192.7h.2M191.7 191.9h.3"/>
<path d="M191.7 192.6h.3M191.7 192.5h.3M191.7 192.4h.3M191.7 192.3h.3M191.7 192.2h.3M191.7 192.1h.3M191.7 192h.3M191.7 191.5h.3M191.7 191.4h.3M191.7 191.3h.3M191.7 191.2h.3M191.7 191.1h.3"/>
<path d="M191.8 191.1h.2M191.9 191h.1M191.9 192.7l-.4 .1M191.9 192.7h-.3M192 192.6h-.3M192.2 192.7l.3 .1M192.2 192.7h.2M192.2 192.6l.2 .1M192.2 192.6h.2M192.2 192.5h.2M192.2 192.4h.2M192.2 192.3h.2"/>
<path d="M192.2 192.2h.2M192.2 192.1h.2M192.2 192h.2M192.2 191.9h.2M192.2 191.8h.2M192.2 191.7h.2M192.2 191.6h.2M192.2 192.8h1.2M192.2 192.9h1.1M192.3 192.9h1M192.3 191.5h.1M192.3 193h.4"/>
<path d="M192.6 193h.1M192.6 192.8h.4M192.6 192.7h.3M192.7 192.6h.2M192.7 192.5h.2M192.7 192.4h.2M192.7 192.3h.2M192.7 192.2h.2M192.7 192.1h.2M192.7 192h.2M192.7 191.9h.2M192.7 191.8h.2"/>
<path d="M192.7 191.7h.2M192.7 191.6h.2M192.8 193h.4M192.8 191.5h.1M193.1 192.8h.3M193.2 192.7h.2M193.2 192.6h.2M193.2 192.5h.2M193.2 192.4h.2M193.2 192.3h.2M193.2 192.2h.2M193.2 192.1h.2"/>
<path d="M193.2 192h.2M193.2 191.9h.2M193.2 191.8h.2M193.2 191.7h.2M193.2 191.6h.2M193.3 191.6h.1M193.3 191.5h.1M193.4 192.8h-1.2M193.6 192.7h.3M193.6 192.6h.2M193.6 192h.2M193.6 191.9h.2"/>
<path d="M193.6 192.7l.4 .1M193.6 192.1h.1M193.7 192.8h.5M193.7 191.8h.2M193.7 192.8h.6M193.7 191.7h.8M193.7 192.9h.6M193.8 191.7h.7M193.8 192.9h.5M193.8 192l-.2 .1M193.8 191.6h.6M193.8 192h-.2"/>
<path d="M193.8 193h.5M193.8 192.3h.8M193.9 191.9h-.3M193.9 191.6h.5M193.9 192.5h-.3M193.9 192.2h.7M194 191.5h.3M194 191.8h-.3M194 192.4h-.3M194 192.2h.6M194.1 193h.1M194.1 192.8h.1"/>
<path d="M194.2 192.4h-.5M194.2 192.1h.4M194.2 192.3h-.5M194.2 191.8h.4M194.3 191.8h.3M194.4 191.9h.2M194.4 192h.2M194.4 192.8h.2M194.4 192.7h.2M194.4 192.6h.2M194.4 192.5h.2M194.4 192.4h.2"/>
<path d="M194.4 192.3h.2M194.5 193h-.1M194.6 192.9h-.2M194.6 192.3h-.8M194.9 192.9h.2M194.9 192.8h.2M194.9 192.7h.2M194.9 192.6h.2M194.9 192.5h.2M194.9 192.4h.2M194.9 192.3h.2M194.9 192.2h.2"/>
<path d="M194.9 192.1h.2M194.9 192h.2M194.9 191.9h.3M195 193h.1M195 191.9h.2M195 191.7h.9M195 191.7h.8M195.1 193h-.2M195.1 191.7h.7M195.1 191.6h.6M195.1 192.9h-.2M195.2 192h-.3"/>
<path d="M195.2 191.6h.5M195.2 191.8l-.2 .1M195.3 191.5h.3M195.3 191.8h-.3M195.6 191.8h.3M195.6 191.8l.3 .1M195.7 191.9h.2M195.7 192h.2M195.9 192l-.2 .1M195.9 192h-.2M196.3 192.6h.2M196.3 192.5h.2"/>
<path d="M196.3 192.2h.8M196.3 192.2h.2M196.3 192.1h.2M196.3 192h.2M196.3 191.9h.2M196.3 192.7h.3M196.3 192.6l.2 .1M196.3 192.7l.4 .1M196.3 192.8h.9M196.4 191.7h.8M196.4 191.7h.7M196.4 192.9h.7"/>
<path d="M196.4 191.6h.7M196.5 192.9h.5M196.5 191.6h.5M196.5 193h.5M196.5 192.5h-.2M196.6 191.8l-.3 .1M196.6 191.5h.3M196.6 192.4h-.3M196.6 191.8h-.3M196.7 193h.1M196.7 191.7h-.4M196.8 192.1h.5"/>
<path d="M196.8 192.4h-.5M196.8 191.7h.4M196.8 192.3h-.5M196.9 191.8h.3M197 192.3h-.7M197 192h.3M197 191.8l.3 .1M197 192.6h.2M197 191.9h.3M197 192.6h.3M197.1 192.5h.2M197.1 192.4h.2"/>
<path d="M197.1 192.8h-.7M197.2 192.2h-.6M197.2 192.7l-.4 .1M197.2 192.4h.1M197.2 192.7h-.3M197.2 192.2h-.5M217.9 197.1v2.8M252.5 197.1v2.8M287.2 197h.1"/>
<circle cx="16.5" cy="177.6" r="1.48"/>
<circle cx="16.5" cy="177.6" r=".38"/>
<circle cx="44.3" cy="177.6" r="1.48"/>
<circle cx="44.3" cy="177.6" r=".38"/>
<circle cx="16.5" cy="188.8" r="1.48"/>
<circle cx="16.5" cy="188.8" r=".38"/>
<circle cx="44.3" cy="188.8" r="1.48"/>
<circle cx="44.3" cy="188.8" r=".38"/>
</g>
<path d="M160.2 64.6h3.7v61.1h-3.7zM199.1 64.6h3.7v61.1h-3.7zM238 64.6h3.7v61.1h-3.7z" fill="none" stroke="#000" stroke-width=".32"/>
<g fill="none" stroke="#000" stroke-width=".47">
<path d="M10 12.6h277.2v184.5h-277.2zM161.1 79.4h.9M161.1 77.5h.9M161.1 75.7h.9M161.1 73.8h.9M161.1 72h.9M161.1 70.1h.9M161.1 68.3h.9M161.1 66.4h.9M200 79.4h1M200 77.5h1M200 75.7h1"/>
<path d="M200 73.8h1M200 72h1M200 70.1h1M200 68.3h1M200 66.4h1M239 79.4h.9M239 77.5h.9M239 75.7h.9M239 73.8h.9M239 72h.9M239 70.1h.9M239 68.3h.9"/>
<path d="M239 66.4h.9M161.1 99.8h.9M161.1 97.9h.9M161.1 96.1h.9M161.1 94.2h.9M161.1 92.4h.9M161.1 90.5h.9M161.1 88.6h.9M161.1 86.8h.9M161.1 84.9h.9M161.1 83.1h.9M161.1 81.2h.9"/>
<path d="M200 99.8h1M200 97.9h1M200 96.1h1M200 94.2h1M200 92.4h1M200 90.5h1M200 88.6h1M200 86.8h1M200 84.9h1M200 83.1h1M200 81.2h1M239 99.8h.9"/>
<path d="M239 97.9h.9M239 96.1h.9M239 94.2h.9M239 92.4h.9M239 90.5h.9M239 88.6h.9M239 86.8h.9M239 84.9h.9M239 83.1h.9M239 81.2h.9M161.1 118.3h.9M161.1 116.5h.9"/>
<path d="M161.1 114.6h.9M161.1 112.8h.9M161.1 110.9h.9M161.1 109h.9M161.1 107.2h.9M161.1 105.3h.9M161.1 103.5h.9M161.1 101.6h.9M200 118.3h1M200 116.5h1M200 114.6h1M200 112.8h1"/>
<path d="M200 110.9h1M200 109h1M200 107.2h1M200 105.3h1M200 103.5h1M200 101.6h1M239 118.3h.9M239 116.5h.9M239 114.6h.9M239 112.8h.9M239 110.9h.9M239 109h.9"/>
<path d="M239 107.2h.9M239 105.3h.9M239 103.5h.9M239 101.6h.9M161.1 123.9h.9M161.1 122h.9M161.1 120.2h.9M200 123.9h1M200 122h1M200 120.2h1M239 123.9h.9M239 122h.9"/>
<path d="M239 120.2h.9M224.1 174.9v22.2M287.2 174.9h-85.3v22.2"/>
</g>
<g fill="none" stroke="#000" stroke-width=".19">
<path d="M106.4 149.4l.9-1.4 1 1.4M113.8 149.4l.9-1.4 1 1.4M121.1 153.5h2.2v.7h-2.2zM121.2 149.4l1-1.4 .9 1.4M128.5 153.5h2.2v.7h-2.2zM128.7 149.4l.9-1.4 .9 1.4M105.9 161h2.8M113.3 161h2.8M120.8 161h2.7M128.2 161h2.8M224.1 178.6h63.1M224.1 182.3h63.1"/>
<path d="M224.1 186h63.1M224.1 189.7h63.1M266.8 186v3.7M287.2 192.5v.9h-63.1"/>
</g>
<path d="M7.2 9.9h282.7v190h-282.7z" fill="none" stroke="#000" stroke-width=".23"/>
<g fill="#000" stroke="#000" stroke-width=".18">
<path d="M68.4 66.2h2v.4h-2zM68.4 68.1h2v.4h-2zM68.4 69.9h2v.4h-2zM68.4 71.8h2v.4h-2zM68.4 73.6h2v.4h-2zM68.4 75.5h2v.4h-2zM68.4 77.3h2v.4h-2zM68.4 79.2h2v.4h-2zM96.2 66.2h2v.4h-2zM96.2 68.1h2v.4h-2zM96.2 69.9h2v.4h-2zM96.2 71.8h2v.4h-2z"/>
<path d="M96.2 73.6h2v.4h-2zM96.2 75.5h2v.4h-2zM96.2 77.3h2v.4h-2zM96.2 79.2h2v.4h-2zM68.4 81h2v.4h-2zM68.4 82.9h2v.4h-2zM68.4 84.8h2v.3h-2zM68.4 86.6h2v.4h-2zM68.4 88.5h2v.3h-2zM68.4 90.3h2v.4h-2zM68.4 92.2h2v.3h-2zM68.4 94h2v.4h-2z"/>
<path d="M68.4 95.9h2v.3h-2zM68.4 97.7h2v.4h-2zM68.4 99.6h2v.4h-2zM96.2 81h2v.4h-2zM96.2 82.9h2v.4h-2zM96.2 84.8h2v.3h-2zM96.2 86.6h2v.4h-2zM96.2 88.5h2v.3h-2zM96.2 90.3h2v.4h-2zM96.2 92.2h2v.3h-2zM96.2 94h2v.4h-2zM96.2 95.9h2v.3h-2z"/>
<path d="M96.2 97.7h2v.4h-2zM96.2 99.6h2v.4h-2zM68.4 101.4h2v.4h-2zM68.4 103.3h2v.4h-2zM68.4 105.1h2v.4h-2zM68.4 107h2v.4h-2zM68.4 108.8h2v.4h-2zM68.4 110.7h2v.4h-2zM68.4 112.6h2v.3h-2zM68.4 114.4h2v.4h-2zM68.4 116.3h2v.3h-2zM68.4 118.1h2v.4h-2z"/>
<path d="M68.4 120h2v.4h-2zM96.2 101.4h2v.4h-2zM96.2 103.3h2v.4h-2zM96.2 105.1h2v.4h-2zM96.2 107h2v.4h-2zM96.2 108.8h2v.4h-2zM96.2 110.7h2v.4h-2zM96.2 112.6h2v.3h-2zM96.2 114.4h2v.4h-2zM96.2 116.3h2v.3h-2zM96.2 118.1h2v.4h-2zM96.2 120h2v.4h-2z"/>
<path d="M68.4 121.8h2v.4h-2zM68.4 123.7h2v.4h-2zM68.4 125.5h2v.4h-2zM68.4 127.4h2v.4h-2zM68.4 129.2h2v.4h-2zM68.4 131.1h2v.4h-2zM68.4 132.9h2v.4h-2zM68.4 134.8h2v.4h-2zM68.4 136.7h2v.3h-2zM68.4 138.5h2v.4h-2zM96.2 121.8h2v.4h-2zM96.2 123.7h2v.4h-2z"/>
<path d="M96.2 125.5h2v.4h-2zM96.2 127.4h2v.4h-2zM96.2 129.2h2v.4h-2zM96.2 131.1h2v.4h-2zM96.2 132.9h2v.4h-2zM96.2 134.8h2v.4h-2zM96.2 136.7h2v.3h-2zM96.2 138.5h2v.4h-2zM105.9 154.6h2.9v.4h-2.9zM105.9 153.9h2.9v.4h-2.9zM113.3 154.6h2.9v.4h-2.9zM113.3 153.9h2.9v.4h-2.9z"/>
<path d="M120.9 154.7h2.5v.7h-2.5zM128.4 154.7h2.4v.7h-2.4z"/>
</g>
<g fill="none" stroke="#000" stroke-width=".3">
<path d="M184.8 187.3h2.9M184.8 187.1h2.8M184.8 186.8h2.8M184.8 186.6h2.8M185.4 186.3h2.3M185.6 184.4h1.6M185.7 189.5h1.4M185.8 189.3h2.1M185.8 184.6h6.2M185.8 184.1h1.1M185.9 189.8h.9M186 189h2"/>
<path d="M186 184.8h5.8M186.1 183.9h.5M186.1 187.6h1.7M186.2 188.8h1.9M186.2 186.1h1.7M186.2 190h.3M186.2 187.8h1.8M186.2 185.8h2M186.2 185.1h5.4M186.3 188h2M186.3 183.6l1.1 .9 .9-.4M186.3 183.6l-.7 .7 .9 1.1-.4 .8-1.3 .2v1l1.3 .1 .1 .4"/>
<path d="M186.3 183.6h.1M186.4 185.6h5.1M186.4 188.6h1.8M186.4 188.3h1.9M186.4 185.3h5M187.6 184.4h2.6M187.8 189.5h.1M188.2 184.1h1.4M188.3 184.1l.1-1.3h1l.1 1.3M188.3 183.9h1.2M188.3 183.6h1.2M188.3 183.4h1.2"/>
<path d="M188.4 183.1h1M188.4 182.9h1M188.8 185.6a1.3 1.3 0 0 0-1.2 1.1 1.3 1.3 0 0 0 .8 1.4l-.6 1.4-.4-.2-1.1 .9-.7-.7 .9-1.1-.3-.5M189 185.6l.6 .2M189.5 188.3h1.9M189.5 188h2M189.6 188.6h1.8M189.6 185.8a1.31 1.31 0 0 1-.2 2.3l.6 1.4 .4-.2 1.1 .9 .7-.7-.9-1.1 .3-.5M189.7 185.8h1.9M189.7 188.8h1.9M189.8 189h2M189.8 187.8h1.8"/>
<path d="M189.9 189.3h2.1M189.9 186.1h1.7M190 189.5h.1M190 187.6h1.7M190.1 186.3h2.3M190.1 187.3h2.9M190.2 186.6h2.8M190.2 187.1h2.8M190.2 186.8h2.8M190.6 184.4h1.6M190.7 189.5h1.4M190.9 184.1h1.1"/>
<path d="M191 189.8h.9M191.2 183.9h.5M191.3 190h.3M191.5 183.6l.7 .7-.9 1.1 .4 .8 1.3 .2v1l-1.3 .1-.1 .4M191.5 183.6l-1.1 .9-.9-.4M191.5 183.6h.1"/>
</g>
<g fill="#000" stroke="#000" stroke-width=".18">
<path d="M15 177.6h1.1l.4 .4v1.1a1.45 1.45 0 0 1-1.5-1.5z" fill-rule="evenodd"/>
<path d="M16.5 176.1a1.45 1.45 0 0 1 1.5 1.5h-1.2l-.1-.2-.2-.1z" fill-rule="evenodd"/>
<path d="M43.2 176.6l.6-.4 .5-.1v1.2l-.3 .1-.1 .2h-1.1l.1-.5z" fill-rule="evenodd"/>
<path d="M44.7 177.6h1.1a1.45 1.45 0 0 1-1.5 1.5v-1.1l.3-.1z" fill-rule="evenodd"/>
<path d="M15 188.8h1.1l.1 .2 .3 .1v1.1a1.48 1.48 0 0 1-1.5-1.4z" fill-rule="evenodd"/>
<path d="M16.5 187.3a1.48 1.48 0 0 1 1.5 1.5h-1.2l-.1-.3-.2-.1z" fill-rule="evenodd"/>
<path d="M43.2 187.7l.6-.4h.5v1.1l-.3 .1-.1 .3h-1.1l.1-.5z" fill-rule="evenodd"/>
<path d="M44.3 189.1l.3-.1 .1-.2h1.1a1.48 1.48 0 0 1-1.5 1.4z" fill-rule="evenodd"/>
</g>
<path d="M125.9 94.2h-3.7l-1.9 1.9v33.3" fill="none" stroke="#000" stroke-width=".57"/>
<use href="#words"/>
</svg>
